VERSION 5.8 ;
BUSBITCHARS "[]" ;
DIVIDERCHAR "/" ;
UNITS
    DATABASE MICRONS 1000 ;
END UNITS

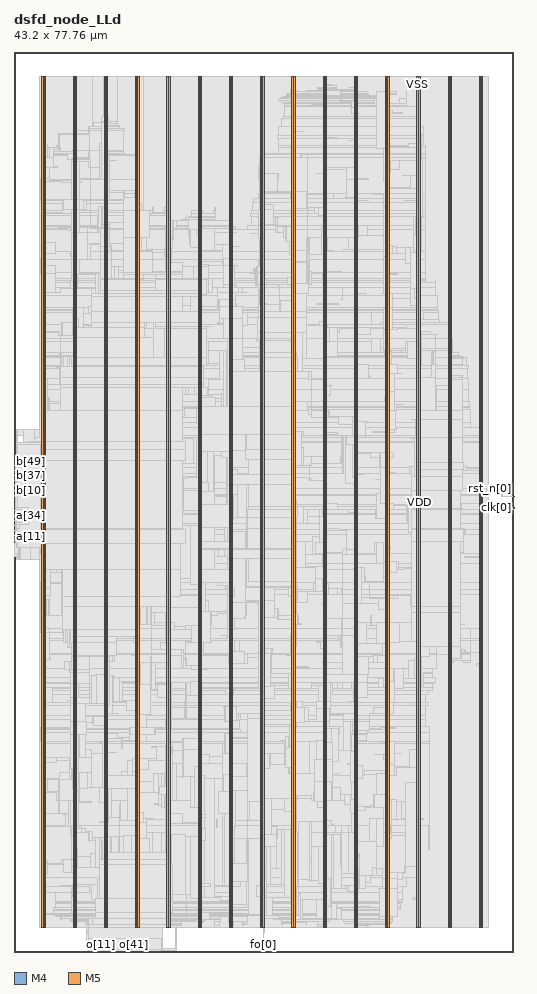
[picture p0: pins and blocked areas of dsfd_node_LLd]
MACRO dsfd_node_LLd
  FOREIGN dsfd_node_LLd 0 0 ;
  CLASS BLOCK ;
  SIZE 43.2 BY 77.76 ;
  PIN a[0]
    DIRECTION INPUT ;
    USE SIGNAL ;
    PORT
      LAYER M4 ;
        RECT  0 35.376 0.084 35.4 ;
    END
  END a[0]
  PIN a[10]
    DIRECTION INPUT ;
    USE SIGNAL ;
    PORT
      LAYER M4 ;
        RECT  0 35.856 0.084 35.88 ;
    END
  END a[10]
  PIN a[11]
    DIRECTION INPUT ;
    USE SIGNAL ;
    PORT
      LAYER M4 ;
        RECT  0 35.904 0.084 35.928 ;
    END
  END a[11]
  PIN a[12]
    DIRECTION INPUT ;
    USE SIGNAL ;
    PORT
      LAYER M4 ;
        RECT  0 35.952 0.084 35.976 ;
    END
  END a[12]
  PIN a[13]
    DIRECTION INPUT ;
    USE SIGNAL ;
    PORT
      LAYER M4 ;
        RECT  0 36 0.084 36.024 ;
    END
  END a[13]
  PIN a[14]
    DIRECTION INPUT ;
    USE SIGNAL ;
    PORT
      LAYER M4 ;
        RECT  0 36.048 0.084 36.072 ;
    END
  END a[14]
  PIN a[15]
    DIRECTION INPUT ;
    USE SIGNAL ;
    PORT
      LAYER M4 ;
        RECT  0 36.096 0.084 36.12 ;
    END
  END a[15]
  PIN a[16]
    DIRECTION INPUT ;
    USE SIGNAL ;
    PORT
      LAYER M4 ;
        RECT  0 36.144 0.084 36.168 ;
    END
  END a[16]
  PIN a[17]
    DIRECTION INPUT ;
    USE SIGNAL ;
    PORT
      LAYER M4 ;
        RECT  0 36.192 0.084 36.216 ;
    END
  END a[17]
  PIN a[18]
    DIRECTION INPUT ;
    USE SIGNAL ;
    PORT
      LAYER M4 ;
        RECT  0 36.24 0.084 36.264 ;
    END
  END a[18]
  PIN a[19]
    DIRECTION INPUT ;
    USE SIGNAL ;
    PORT
      LAYER M4 ;
        RECT  0 36.288 0.084 36.312 ;
    END
  END a[19]
  PIN a[1]
    DIRECTION INPUT ;
    USE SIGNAL ;
    PORT
      LAYER M4 ;
        RECT  0 35.424 0.084 35.448 ;
    END
  END a[1]
  PIN a[20]
    DIRECTION INPUT ;
    USE SIGNAL ;
    PORT
      LAYER M4 ;
        RECT  0 36.336 0.084 36.36 ;
    END
  END a[20]
  PIN a[21]
    DIRECTION INPUT ;
    USE SIGNAL ;
    PORT
      LAYER M4 ;
        RECT  0 36.384 0.084 36.408 ;
    END
  END a[21]
  PIN a[22]
    DIRECTION INPUT ;
    USE SIGNAL ;
    PORT
      LAYER M4 ;
        RECT  0 36.432 0.084 36.456 ;
    END
  END a[22]
  PIN a[23]
    DIRECTION INPUT ;
    USE SIGNAL ;
    PORT
      LAYER M4 ;
        RECT  0 36.48 0.084 36.504 ;
    END
  END a[23]
  PIN a[24]
    DIRECTION INPUT ;
    USE SIGNAL ;
    PORT
      LAYER M4 ;
        RECT  0 36.528 0.084 36.552 ;
    END
  END a[24]
  PIN a[25]
    DIRECTION INPUT ;
    USE SIGNAL ;
    PORT
      LAYER M4 ;
        RECT  0 36.576 0.084 36.6 ;
    END
  END a[25]
  PIN a[26]
    DIRECTION INPUT ;
    USE SIGNAL ;
    PORT
      LAYER M4 ;
        RECT  0 36.624 0.084 36.648 ;
    END
  END a[26]
  PIN a[27]
    DIRECTION INPUT ;
    USE SIGNAL ;
    PORT
      LAYER M4 ;
        RECT  0 36.672 0.084 36.696 ;
    END
  END a[27]
  PIN a[28]
    DIRECTION INPUT ;
    USE SIGNAL ;
    PORT
      LAYER M4 ;
        RECT  0 36.72 0.084 36.744 ;
    END
  END a[28]
  PIN a[29]
    DIRECTION INPUT ;
    USE SIGNAL ;
    PORT
      LAYER M4 ;
        RECT  0 36.768 0.084 36.792 ;
    END
  END a[29]
  PIN a[2]
    DIRECTION INPUT ;
    USE SIGNAL ;
    PORT
      LAYER M4 ;
        RECT  0 35.472 0.084 35.496 ;
    END
  END a[2]
  PIN a[30]
    DIRECTION INPUT ;
    USE SIGNAL ;
    PORT
      LAYER M4 ;
        RECT  0 36.816 0.084 36.84 ;
    END
  END a[30]
  PIN a[31]
    DIRECTION INPUT ;
    USE SIGNAL ;
    PORT
      LAYER M4 ;
        RECT  0 36.864 0.084 36.888 ;
    END
  END a[31]
  PIN a[32]
    DIRECTION INPUT ;
    USE SIGNAL ;
    PORT
      LAYER M4 ;
        RECT  0 36.912 0.084 36.936 ;
    END
  END a[32]
  PIN a[33]
    DIRECTION INPUT ;
    USE SIGNAL ;
    PORT
      LAYER M4 ;
        RECT  0 36.96 0.084 36.984 ;
    END
  END a[33]
  PIN a[34]
    DIRECTION INPUT ;
    USE SIGNAL ;
    PORT
      LAYER M4 ;
        RECT  0 37.008 0.084 37.032 ;
    END
  END a[34]
  PIN a[35]
    DIRECTION INPUT ;
    USE SIGNAL ;
    PORT
      LAYER M4 ;
        RECT  0 37.056 0.084 37.08 ;
    END
  END a[35]
  PIN a[36]
    DIRECTION INPUT ;
    USE SIGNAL ;
    PORT
      LAYER M4 ;
        RECT  0 37.104 0.084 37.128 ;
    END
  END a[36]
  PIN a[37]
    DIRECTION INPUT ;
    USE SIGNAL ;
    PORT
      LAYER M4 ;
        RECT  0 37.152 0.084 37.176 ;
    END
  END a[37]
  PIN a[38]
    DIRECTION INPUT ;
    USE SIGNAL ;
    PORT
      LAYER M4 ;
        RECT  0 37.2 0.084 37.224 ;
    END
  END a[38]
  PIN a[39]
    DIRECTION INPUT ;
    USE SIGNAL ;
    PORT
      LAYER M4 ;
        RECT  0 37.248 0.084 37.272 ;
    END
  END a[39]
  PIN a[3]
    DIRECTION INPUT ;
    USE SIGNAL ;
    PORT
      LAYER M4 ;
        RECT  0 35.52 0.084 35.544 ;
    END
  END a[3]
  PIN a[40]
    DIRECTION INPUT ;
    USE SIGNAL ;
    PORT
      LAYER M4 ;
        RECT  0 37.296 0.084 37.32 ;
    END
  END a[40]
  PIN a[41]
    DIRECTION INPUT ;
    USE SIGNAL ;
    PORT
      LAYER M4 ;
        RECT  0 37.344 0.084 37.368 ;
    END
  END a[41]
  PIN a[42]
    DIRECTION INPUT ;
    USE SIGNAL ;
    PORT
      LAYER M4 ;
        RECT  0 37.392 0.084 37.416 ;
    END
  END a[42]
  PIN a[43]
    DIRECTION INPUT ;
    USE SIGNAL ;
    PORT
      LAYER M4 ;
        RECT  0 37.44 0.084 37.464 ;
    END
  END a[43]
  PIN a[44]
    DIRECTION INPUT ;
    USE SIGNAL ;
    PORT
      LAYER M4 ;
        RECT  0 37.488 0.084 37.512 ;
    END
  END a[44]
  PIN a[45]
    DIRECTION INPUT ;
    USE SIGNAL ;
    PORT
      LAYER M4 ;
        RECT  0 37.536 0.084 37.56 ;
    END
  END a[45]
  PIN a[46]
    DIRECTION INPUT ;
    USE SIGNAL ;
    PORT
      LAYER M4 ;
        RECT  0 37.584 0.084 37.608 ;
    END
  END a[46]
  PIN a[47]
    DIRECTION INPUT ;
    USE SIGNAL ;
    PORT
      LAYER M4 ;
        RECT  0 37.632 0.084 37.656 ;
    END
  END a[47]
  PIN a[48]
    DIRECTION INPUT ;
    USE SIGNAL ;
    PORT
      LAYER M4 ;
        RECT  0 37.68 0.084 37.704 ;
    END
  END a[48]
  PIN a[49]
    DIRECTION INPUT ;
    USE SIGNAL ;
    PORT
      LAYER M4 ;
        RECT  0 37.728 0.084 37.752 ;
    END
  END a[49]
  PIN a[4]
    DIRECTION INPUT ;
    USE SIGNAL ;
    PORT
      LAYER M4 ;
        RECT  0 35.568 0.084 35.592 ;
    END
  END a[4]
  PIN a[50]
    DIRECTION INPUT ;
    USE SIGNAL ;
    PORT
      LAYER M4 ;
        RECT  0 37.776 0.084 37.8 ;
    END
  END a[50]
  PIN a[51]
    DIRECTION INPUT ;
    USE SIGNAL ;
    PORT
      LAYER M4 ;
        RECT  0 37.824 0.084 37.848 ;
    END
  END a[51]
  PIN a[52]
    DIRECTION INPUT ;
    USE SIGNAL ;
    PORT
      LAYER M4 ;
        RECT  0 37.872 0.084 37.896 ;
    END
  END a[52]
  PIN a[53]
    DIRECTION INPUT ;
    USE SIGNAL ;
    PORT
      LAYER M4 ;
        RECT  0 37.92 0.084 37.944 ;
    END
  END a[53]
  PIN a[54]
    DIRECTION INPUT ;
    USE SIGNAL ;
    PORT
      LAYER M4 ;
        RECT  0 37.968 0.084 37.992 ;
    END
  END a[54]
  PIN a[55]
    DIRECTION INPUT ;
    USE SIGNAL ;
    PORT
      LAYER M4 ;
        RECT  0 38.016 0.084 38.04 ;
    END
  END a[55]
  PIN a[56]
    DIRECTION INPUT ;
    USE SIGNAL ;
    PORT
      LAYER M4 ;
        RECT  0 38.064 0.084 38.088 ;
    END
  END a[56]
  PIN a[57]
    DIRECTION INPUT ;
    USE SIGNAL ;
    PORT
      LAYER M4 ;
        RECT  0 38.112 0.084 38.136 ;
    END
  END a[57]
  PIN a[58]
    DIRECTION INPUT ;
    USE SIGNAL ;
    PORT
      LAYER M4 ;
        RECT  0 38.16 0.084 38.184 ;
    END
  END a[58]
  PIN a[59]
    DIRECTION INPUT ;
    USE SIGNAL ;
    PORT
      LAYER M4 ;
        RECT  0 38.208 0.084 38.232 ;
    END
  END a[59]
  PIN a[5]
    DIRECTION INPUT ;
    USE SIGNAL ;
    PORT
      LAYER M4 ;
        RECT  0 35.616 0.084 35.64 ;
    END
  END a[5]
  PIN a[60]
    DIRECTION INPUT ;
    USE SIGNAL ;
    PORT
      LAYER M4 ;
        RECT  0 38.256 0.084 38.28 ;
    END
  END a[60]
  PIN a[61]
    DIRECTION INPUT ;
    USE SIGNAL ;
    PORT
      LAYER M4 ;
        RECT  0 38.304 0.084 38.328 ;
    END
  END a[61]
  PIN a[62]
    DIRECTION INPUT ;
    USE SIGNAL ;
    PORT
      LAYER M4 ;
        RECT  0 38.352 0.084 38.376 ;
    END
  END a[62]
  PIN a[6]
    DIRECTION INPUT ;
    USE SIGNAL ;
    PORT
      LAYER M4 ;
        RECT  0 35.664 0.084 35.688 ;
    END
  END a[6]
  PIN a[7]
    DIRECTION INPUT ;
    USE SIGNAL ;
    PORT
      LAYER M4 ;
        RECT  0 35.712 0.084 35.736 ;
    END
  END a[7]
  PIN a[8]
    DIRECTION INPUT ;
    USE SIGNAL ;
    PORT
      LAYER M4 ;
        RECT  0 35.76 0.084 35.784 ;
    END
  END a[8]
  PIN a[9]
    DIRECTION INPUT ;
    USE SIGNAL ;
    PORT
      LAYER M4 ;
        RECT  0 35.808 0.084 35.832 ;
    END
  END a[9]
  PIN b[0]
    DIRECTION INPUT ;
    USE SIGNAL ;
    PORT
      LAYER M4 ;
        RECT  0 39.36 0.084 39.384 ;
    END
  END b[0]
  PIN b[10]
    DIRECTION INPUT ;
    USE SIGNAL ;
    PORT
      LAYER M4 ;
        RECT  0 39.84 0.084 39.864 ;
    END
  END b[10]
  PIN b[11]
    DIRECTION INPUT ;
    USE SIGNAL ;
    PORT
      LAYER M4 ;
        RECT  0 39.888 0.084 39.912 ;
    END
  END b[11]
  PIN b[12]
    DIRECTION INPUT ;
    USE SIGNAL ;
    PORT
      LAYER M4 ;
        RECT  0 39.936 0.084 39.96 ;
    END
  END b[12]
  PIN b[13]
    DIRECTION INPUT ;
    USE SIGNAL ;
    PORT
      LAYER M4 ;
        RECT  0 39.984 0.084 40.008 ;
    END
  END b[13]
  PIN b[14]
    DIRECTION INPUT ;
    USE SIGNAL ;
    PORT
      LAYER M4 ;
        RECT  0 40.032 0.084 40.056 ;
    END
  END b[14]
  PIN b[15]
    DIRECTION INPUT ;
    USE SIGNAL ;
    PORT
      LAYER M4 ;
        RECT  0 40.08 0.084 40.104 ;
    END
  END b[15]
  PIN b[16]
    DIRECTION INPUT ;
    USE SIGNAL ;
    PORT
      LAYER M4 ;
        RECT  0 40.128 0.084 40.152 ;
    END
  END b[16]
  PIN b[17]
    DIRECTION INPUT ;
    USE SIGNAL ;
    PORT
      LAYER M4 ;
        RECT  0 40.176 0.084 40.2 ;
    END
  END b[17]
  PIN b[18]
    DIRECTION INPUT ;
    USE SIGNAL ;
    PORT
      LAYER M4 ;
        RECT  0 40.224 0.084 40.248 ;
    END
  END b[18]
  PIN b[19]
    DIRECTION INPUT ;
    USE SIGNAL ;
    PORT
      LAYER M4 ;
        RECT  0 40.272 0.084 40.296 ;
    END
  END b[19]
  PIN b[1]
    DIRECTION INPUT ;
    USE SIGNAL ;
    PORT
      LAYER M4 ;
        RECT  0 39.408 0.084 39.432 ;
    END
  END b[1]
  PIN b[20]
    DIRECTION INPUT ;
    USE SIGNAL ;
    PORT
      LAYER M4 ;
        RECT  0 40.32 0.084 40.344 ;
    END
  END b[20]
  PIN b[21]
    DIRECTION INPUT ;
    USE SIGNAL ;
    PORT
      LAYER M4 ;
        RECT  0 40.368 0.084 40.392 ;
    END
  END b[21]
  PIN b[22]
    DIRECTION INPUT ;
    USE SIGNAL ;
    PORT
      LAYER M4 ;
        RECT  0 40.416 0.084 40.44 ;
    END
  END b[22]
  PIN b[23]
    DIRECTION INPUT ;
    USE SIGNAL ;
    PORT
      LAYER M4 ;
        RECT  0 40.464 0.084 40.488 ;
    END
  END b[23]
  PIN b[24]
    DIRECTION INPUT ;
    USE SIGNAL ;
    PORT
      LAYER M4 ;
        RECT  0 40.512 0.084 40.536 ;
    END
  END b[24]
  PIN b[25]
    DIRECTION INPUT ;
    USE SIGNAL ;
    PORT
      LAYER M4 ;
        RECT  0 40.56 0.084 40.584 ;
    END
  END b[25]
  PIN b[26]
    DIRECTION INPUT ;
    USE SIGNAL ;
    PORT
      LAYER M4 ;
        RECT  0 40.608 0.084 40.632 ;
    END
  END b[26]
  PIN b[27]
    DIRECTION INPUT ;
    USE SIGNAL ;
    PORT
      LAYER M4 ;
        RECT  0 40.656 0.084 40.68 ;
    END
  END b[27]
  PIN b[28]
    DIRECTION INPUT ;
    USE SIGNAL ;
    PORT
      LAYER M4 ;
        RECT  0 40.704 0.084 40.728 ;
    END
  END b[28]
  PIN b[29]
    DIRECTION INPUT ;
    USE SIGNAL ;
    PORT
      LAYER M4 ;
        RECT  0 40.752 0.084 40.776 ;
    END
  END b[29]
  PIN b[2]
    DIRECTION INPUT ;
    USE SIGNAL ;
    PORT
      LAYER M4 ;
        RECT  0 39.456 0.084 39.48 ;
    END
  END b[2]
  PIN b[30]
    DIRECTION INPUT ;
    USE SIGNAL ;
    PORT
      LAYER M4 ;
        RECT  0 40.8 0.084 40.824 ;
    END
  END b[30]
  PIN b[31]
    DIRECTION INPUT ;
    USE SIGNAL ;
    PORT
      LAYER M4 ;
        RECT  0 40.848 0.084 40.872 ;
    END
  END b[31]
  PIN b[32]
    DIRECTION INPUT ;
    USE SIGNAL ;
    PORT
      LAYER M4 ;
        RECT  0 40.896 0.084 40.92 ;
    END
  END b[32]
  PIN b[33]
    DIRECTION INPUT ;
    USE SIGNAL ;
    PORT
      LAYER M4 ;
        RECT  0 40.944 0.084 40.968 ;
    END
  END b[33]
  PIN b[34]
    DIRECTION INPUT ;
    USE SIGNAL ;
    PORT
      LAYER M4 ;
        RECT  0 40.992 0.084 41.016 ;
    END
  END b[34]
  PIN b[35]
    DIRECTION INPUT ;
    USE SIGNAL ;
    PORT
      LAYER M4 ;
        RECT  0 41.04 0.084 41.064 ;
    END
  END b[35]
  PIN b[36]
    DIRECTION INPUT ;
    USE SIGNAL ;
    PORT
      LAYER M4 ;
        RECT  0 41.088 0.084 41.112 ;
    END
  END b[36]
  PIN b[37]
    DIRECTION INPUT ;
    USE SIGNAL ;
    PORT
      LAYER M4 ;
        RECT  0 41.136 0.084 41.16 ;
    END
  END b[37]
  PIN b[38]
    DIRECTION INPUT ;
    USE SIGNAL ;
    PORT
      LAYER M4 ;
        RECT  0 41.184 0.084 41.208 ;
    END
  END b[38]
  PIN b[39]
    DIRECTION INPUT ;
    USE SIGNAL ;
    PORT
      LAYER M4 ;
        RECT  0 41.232 0.084 41.256 ;
    END
  END b[39]
  PIN b[3]
    DIRECTION INPUT ;
    USE SIGNAL ;
    PORT
      LAYER M4 ;
        RECT  0 39.504 0.084 39.528 ;
    END
  END b[3]
  PIN b[40]
    DIRECTION INPUT ;
    USE SIGNAL ;
    PORT
      LAYER M4 ;
        RECT  0 41.28 0.084 41.304 ;
    END
  END b[40]
  PIN b[41]
    DIRECTION INPUT ;
    USE SIGNAL ;
    PORT
      LAYER M4 ;
        RECT  0 41.328 0.084 41.352 ;
    END
  END b[41]
  PIN b[42]
    DIRECTION INPUT ;
    USE SIGNAL ;
    PORT
      LAYER M4 ;
        RECT  0 41.376 0.084 41.4 ;
    END
  END b[42]
  PIN b[43]
    DIRECTION INPUT ;
    USE SIGNAL ;
    PORT
      LAYER M4 ;
        RECT  0 41.424 0.084 41.448 ;
    END
  END b[43]
  PIN b[44]
    DIRECTION INPUT ;
    USE SIGNAL ;
    PORT
      LAYER M4 ;
        RECT  0 41.472 0.084 41.496 ;
    END
  END b[44]
  PIN b[45]
    DIRECTION INPUT ;
    USE SIGNAL ;
    PORT
      LAYER M4 ;
        RECT  0 41.52 0.084 41.544 ;
    END
  END b[45]
  PIN b[46]
    DIRECTION INPUT ;
    USE SIGNAL ;
    PORT
      LAYER M4 ;
        RECT  0 41.568 0.084 41.592 ;
    END
  END b[46]
  PIN b[47]
    DIRECTION INPUT ;
    USE SIGNAL ;
    PORT
      LAYER M4 ;
        RECT  0 41.616 0.084 41.64 ;
    END
  END b[47]
  PIN b[48]
    DIRECTION INPUT ;
    USE SIGNAL ;
    PORT
      LAYER M4 ;
        RECT  0 41.664 0.084 41.688 ;
    END
  END b[48]
  PIN b[49]
    DIRECTION INPUT ;
    USE SIGNAL ;
    PORT
      LAYER M4 ;
        RECT  0 41.712 0.084 41.736 ;
    END
  END b[49]
  PIN b[4]
    DIRECTION INPUT ;
    USE SIGNAL ;
    PORT
      LAYER M4 ;
        RECT  0 39.552 0.084 39.576 ;
    END
  END b[4]
  PIN b[50]
    DIRECTION INPUT ;
    USE SIGNAL ;
    PORT
      LAYER M4 ;
        RECT  0 41.76 0.084 41.784 ;
    END
  END b[50]
  PIN b[51]
    DIRECTION INPUT ;
    USE SIGNAL ;
    PORT
      LAYER M4 ;
        RECT  0 41.808 0.084 41.832 ;
    END
  END b[51]
  PIN b[52]
    DIRECTION INPUT ;
    USE SIGNAL ;
    PORT
      LAYER M4 ;
        RECT  0 41.856 0.084 41.88 ;
    END
  END b[52]
  PIN b[53]
    DIRECTION INPUT ;
    USE SIGNAL ;
    PORT
      LAYER M4 ;
        RECT  0 41.904 0.084 41.928 ;
    END
  END b[53]
  PIN b[54]
    DIRECTION INPUT ;
    USE SIGNAL ;
    PORT
      LAYER M4 ;
        RECT  0 41.952 0.084 41.976 ;
    END
  END b[54]
  PIN b[55]
    DIRECTION INPUT ;
    USE SIGNAL ;
    PORT
      LAYER M4 ;
        RECT  0 42 0.084 42.024 ;
    END
  END b[55]
  PIN b[56]
    DIRECTION INPUT ;
    USE SIGNAL ;
    PORT
      LAYER M4 ;
        RECT  0 42.048 0.084 42.072 ;
    END
  END b[56]
  PIN b[57]
    DIRECTION INPUT ;
    USE SIGNAL ;
    PORT
      LAYER M4 ;
        RECT  0 42.096 0.084 42.12 ;
    END
  END b[57]
  PIN b[58]
    DIRECTION INPUT ;
    USE SIGNAL ;
    PORT
      LAYER M4 ;
        RECT  0 42.144 0.084 42.168 ;
    END
  END b[58]
  PIN b[59]
    DIRECTION INPUT ;
    USE SIGNAL ;
    PORT
      LAYER M4 ;
        RECT  0 42.192 0.084 42.216 ;
    END
  END b[59]
  PIN b[5]
    DIRECTION INPUT ;
    USE SIGNAL ;
    PORT
      LAYER M4 ;
        RECT  0 39.6 0.084 39.624 ;
    END
  END b[5]
  PIN b[60]
    DIRECTION INPUT ;
    USE SIGNAL ;
    PORT
      LAYER M4 ;
        RECT  0 42.24 0.084 42.264 ;
    END
  END b[60]
  PIN b[61]
    DIRECTION INPUT ;
    USE SIGNAL ;
    PORT
      LAYER M4 ;
        RECT  0 42.288 0.084 42.312 ;
    END
  END b[61]
  PIN b[62]
    DIRECTION INPUT ;
    USE SIGNAL ;
    PORT
      LAYER M4 ;
        RECT  0 42.336 0.084 42.36 ;
    END
  END b[62]
  PIN b[6]
    DIRECTION INPUT ;
    USE SIGNAL ;
    PORT
      LAYER M4 ;
        RECT  0 39.648 0.084 39.672 ;
    END
  END b[6]
  PIN b[7]
    DIRECTION INPUT ;
    USE SIGNAL ;
    PORT
      LAYER M4 ;
        RECT  0 39.696 0.084 39.72 ;
    END
  END b[7]
  PIN b[8]
    DIRECTION INPUT ;
    USE SIGNAL ;
    PORT
      LAYER M4 ;
        RECT  0 39.744 0.084 39.768 ;
    END
  END b[8]
  PIN b[9]
    DIRECTION INPUT ;
    USE SIGNAL ;
    PORT
      LAYER M4 ;
        RECT  0 39.792 0.084 39.816 ;
    END
  END b[9]
  PIN clk[0]
    DIRECTION INPUT ;
    USE SIGNAL ;
    PORT
      LAYER M4 ;
        RECT  43.116 38.352 43.2 38.376 ;
    END
  END clk[0]
  PIN fo[0]
    DIRECTION OUTPUT ;
    USE SIGNAL ;
    PORT
      LAYER M5 ;
        RECT  21.552 0 21.576 0.084 ;
    END
  END fo[0]
  PIN o[0]
    DIRECTION OUTPUT ;
    USE SIGNAL ;
    PORT
      LAYER M5 ;
        RECT  6.432 0 6.456 0.084 ;
    END
  END o[0]
  PIN o[10]
    DIRECTION OUTPUT ;
    USE SIGNAL ;
    PORT
      LAYER M5 ;
        RECT  7.392 0 7.416 0.084 ;
    END
  END o[10]
  PIN o[11]
    DIRECTION OUTPUT ;
    USE SIGNAL ;
    PORT
      LAYER M5 ;
        RECT  7.488 0 7.512 0.084 ;
    END
  END o[11]
  PIN o[12]
    DIRECTION OUTPUT ;
    USE SIGNAL ;
    PORT
      LAYER M5 ;
        RECT  7.584 0 7.608 0.084 ;
    END
  END o[12]
  PIN o[13]
    DIRECTION OUTPUT ;
    USE SIGNAL ;
    PORT
      LAYER M5 ;
        RECT  7.68 0 7.704 0.084 ;
    END
  END o[13]
  PIN o[14]
    DIRECTION OUTPUT ;
    USE SIGNAL ;
    PORT
      LAYER M5 ;
        RECT  7.776 0 7.8 0.084 ;
    END
  END o[14]
  PIN o[15]
    DIRECTION OUTPUT ;
    USE SIGNAL ;
    PORT
      LAYER M5 ;
        RECT  7.872 0 7.896 0.084 ;
    END
  END o[15]
  PIN o[16]
    DIRECTION OUTPUT ;
    USE SIGNAL ;
    PORT
      LAYER M5 ;
        RECT  7.968 0 7.992 0.084 ;
    END
  END o[16]
  PIN o[17]
    DIRECTION OUTPUT ;
    USE SIGNAL ;
    PORT
      LAYER M5 ;
        RECT  8.064 0 8.088 0.084 ;
    END
  END o[17]
  PIN o[18]
    DIRECTION OUTPUT ;
    USE SIGNAL ;
    PORT
      LAYER M5 ;
        RECT  8.16 0 8.184 0.084 ;
    END
  END o[18]
  PIN o[19]
    DIRECTION OUTPUT ;
    USE SIGNAL ;
    PORT
      LAYER M5 ;
        RECT  8.256 0 8.28 0.084 ;
    END
  END o[19]
  PIN o[1]
    DIRECTION OUTPUT ;
    USE SIGNAL ;
    PORT
      LAYER M5 ;
        RECT  6.528 0 6.552 0.084 ;
    END
  END o[1]
  PIN o[20]
    DIRECTION OUTPUT ;
    USE SIGNAL ;
    PORT
      LAYER M5 ;
        RECT  8.352 0 8.376 0.084 ;
    END
  END o[20]
  PIN o[21]
    DIRECTION OUTPUT ;
    USE SIGNAL ;
    PORT
      LAYER M5 ;
        RECT  8.448 0 8.472 0.084 ;
    END
  END o[21]
  PIN o[22]
    DIRECTION OUTPUT ;
    USE SIGNAL ;
    PORT
      LAYER M5 ;
        RECT  8.544 0 8.568 0.084 ;
    END
  END o[22]
  PIN o[23]
    DIRECTION OUTPUT ;
    USE SIGNAL ;
    PORT
      LAYER M5 ;
        RECT  8.64 0 8.664 0.084 ;
    END
  END o[23]
  PIN o[24]
    DIRECTION OUTPUT ;
    USE SIGNAL ;
    PORT
      LAYER M5 ;
        RECT  8.736 0 8.76 0.084 ;
    END
  END o[24]
  PIN o[25]
    DIRECTION OUTPUT ;
    USE SIGNAL ;
    PORT
      LAYER M5 ;
        RECT  8.832 0 8.856 0.084 ;
    END
  END o[25]
  PIN o[26]
    DIRECTION OUTPUT ;
    USE SIGNAL ;
    PORT
      LAYER M5 ;
        RECT  8.928 0 8.952 0.084 ;
    END
  END o[26]
  PIN o[27]
    DIRECTION OUTPUT ;
    USE SIGNAL ;
    PORT
      LAYER M5 ;
        RECT  9.024 0 9.048 0.084 ;
    END
  END o[27]
  PIN o[28]
    DIRECTION OUTPUT ;
    USE SIGNAL ;
    PORT
      LAYER M5 ;
        RECT  9.12 0 9.144 0.084 ;
    END
  END o[28]
  PIN o[29]
    DIRECTION OUTPUT ;
    USE SIGNAL ;
    PORT
      LAYER M5 ;
        RECT  9.216 0 9.24 0.084 ;
    END
  END o[29]
  PIN o[2]
    DIRECTION OUTPUT ;
    USE SIGNAL ;
    PORT
      LAYER M5 ;
        RECT  6.624 0 6.648 0.084 ;
    END
  END o[2]
  PIN o[30]
    DIRECTION OUTPUT ;
    USE SIGNAL ;
    PORT
      LAYER M5 ;
        RECT  9.312 0 9.336 0.084 ;
    END
  END o[30]
  PIN o[31]
    DIRECTION OUTPUT ;
    USE SIGNAL ;
    PORT
      LAYER M5 ;
        RECT  9.408 0 9.432 0.084 ;
    END
  END o[31]
  PIN o[32]
    DIRECTION OUTPUT ;
    USE SIGNAL ;
    PORT
      LAYER M5 ;
        RECT  9.504 0 9.528 0.084 ;
    END
  END o[32]
  PIN o[33]
    DIRECTION OUTPUT ;
    USE SIGNAL ;
    PORT
      LAYER M5 ;
        RECT  9.6 0 9.624 0.084 ;
    END
  END o[33]
  PIN o[34]
    DIRECTION OUTPUT ;
    USE SIGNAL ;
    PORT
      LAYER M5 ;
        RECT  9.696 0 9.72 0.084 ;
    END
  END o[34]
  PIN o[35]
    DIRECTION OUTPUT ;
    USE SIGNAL ;
    PORT
      LAYER M5 ;
        RECT  9.792 0 9.816 0.084 ;
    END
  END o[35]
  PIN o[36]
    DIRECTION OUTPUT ;
    USE SIGNAL ;
    PORT
      LAYER M5 ;
        RECT  9.888 0 9.912 0.084 ;
    END
  END o[36]
  PIN o[37]
    DIRECTION OUTPUT ;
    USE SIGNAL ;
    PORT
      LAYER M5 ;
        RECT  9.984 0 10.008 0.084 ;
    END
  END o[37]
  PIN o[38]
    DIRECTION OUTPUT ;
    USE SIGNAL ;
    PORT
      LAYER M5 ;
        RECT  10.08 0 10.104 0.084 ;
    END
  END o[38]
  PIN o[39]
    DIRECTION OUTPUT ;
    USE SIGNAL ;
    PORT
      LAYER M5 ;
        RECT  10.176 0 10.2 0.084 ;
    END
  END o[39]
  PIN o[3]
    DIRECTION OUTPUT ;
    USE SIGNAL ;
    PORT
      LAYER M5 ;
        RECT  6.72 0 6.744 0.084 ;
    END
  END o[3]
  PIN o[40]
    DIRECTION OUTPUT ;
    USE SIGNAL ;
    PORT
      LAYER M5 ;
        RECT  10.272 0 10.296 0.084 ;
    END
  END o[40]
  PIN o[41]
    DIRECTION OUTPUT ;
    USE SIGNAL ;
    PORT
      LAYER M5 ;
        RECT  10.368 0 10.392 0.084 ;
    END
  END o[41]
  PIN o[42]
    DIRECTION OUTPUT ;
    USE SIGNAL ;
    PORT
      LAYER M5 ;
        RECT  10.464 0 10.488 0.084 ;
    END
  END o[42]
  PIN o[43]
    DIRECTION OUTPUT ;
    USE SIGNAL ;
    PORT
      LAYER M5 ;
        RECT  10.56 0 10.584 0.084 ;
    END
  END o[43]
  PIN o[44]
    DIRECTION OUTPUT ;
    USE SIGNAL ;
    PORT
      LAYER M5 ;
        RECT  10.656 0 10.68 0.084 ;
    END
  END o[44]
  PIN o[45]
    DIRECTION OUTPUT ;
    USE SIGNAL ;
    PORT
      LAYER M5 ;
        RECT  10.752 0 10.776 0.084 ;
    END
  END o[45]
  PIN o[46]
    DIRECTION OUTPUT ;
    USE SIGNAL ;
    PORT
      LAYER M5 ;
        RECT  10.848 0 10.872 0.084 ;
    END
  END o[46]
  PIN o[47]
    DIRECTION OUTPUT ;
    USE SIGNAL ;
    PORT
      LAYER M5 ;
        RECT  10.944 0 10.968 0.084 ;
    END
  END o[47]
  PIN o[48]
    DIRECTION OUTPUT ;
    USE SIGNAL ;
    PORT
      LAYER M5 ;
        RECT  11.04 0 11.064 0.084 ;
    END
  END o[48]
  PIN o[49]
    DIRECTION OUTPUT ;
    USE SIGNAL ;
    PORT
      LAYER M5 ;
        RECT  11.136 0 11.16 0.084 ;
    END
  END o[49]
  PIN o[4]
    DIRECTION OUTPUT ;
    USE SIGNAL ;
    PORT
      LAYER M5 ;
        RECT  6.816 0 6.84 0.084 ;
    END
  END o[4]
  PIN o[50]
    DIRECTION OUTPUT ;
    USE SIGNAL ;
    PORT
      LAYER M5 ;
        RECT  11.232 0 11.256 0.084 ;
    END
  END o[50]
  PIN o[51]
    DIRECTION OUTPUT ;
    USE SIGNAL ;
    PORT
      LAYER M5 ;
        RECT  11.328 0 11.352 0.084 ;
    END
  END o[51]
  PIN o[52]
    DIRECTION OUTPUT ;
    USE SIGNAL ;
    PORT
      LAYER M5 ;
        RECT  11.424 0 11.448 0.084 ;
    END
  END o[52]
  PIN o[53]
    DIRECTION OUTPUT ;
    USE SIGNAL ;
    PORT
      LAYER M5 ;
        RECT  11.52 0 11.544 0.084 ;
    END
  END o[53]
  PIN o[54]
    DIRECTION OUTPUT ;
    USE SIGNAL ;
    PORT
      LAYER M5 ;
        RECT  11.616 0 11.64 0.084 ;
    END
  END o[54]
  PIN o[55]
    DIRECTION OUTPUT ;
    USE SIGNAL ;
    PORT
      LAYER M5 ;
        RECT  11.712 0 11.736 0.084 ;
    END
  END o[55]
  PIN o[56]
    DIRECTION OUTPUT ;
    USE SIGNAL ;
    PORT
      LAYER M5 ;
        RECT  11.808 0 11.832 0.084 ;
    END
  END o[56]
  PIN o[57]
    DIRECTION OUTPUT ;
    USE SIGNAL ;
    PORT
      LAYER M5 ;
        RECT  11.904 0 11.928 0.084 ;
    END
  END o[57]
  PIN o[58]
    DIRECTION OUTPUT ;
    USE SIGNAL ;
    PORT
      LAYER M5 ;
        RECT  12 0 12.024 0.084 ;
    END
  END o[58]
  PIN o[59]
    DIRECTION OUTPUT ;
    USE SIGNAL ;
    PORT
      LAYER M5 ;
        RECT  12.096 0 12.12 0.084 ;
    END
  END o[59]
  PIN o[5]
    DIRECTION OUTPUT ;
    USE SIGNAL ;
    PORT
      LAYER M5 ;
        RECT  6.912 0 6.936 0.084 ;
    END
  END o[5]
  PIN o[60]
    DIRECTION OUTPUT ;
    USE SIGNAL ;
    PORT
      LAYER M5 ;
        RECT  12.192 0 12.216 0.084 ;
    END
  END o[60]
  PIN o[61]
    DIRECTION OUTPUT ;
    USE SIGNAL ;
    PORT
      LAYER M5 ;
        RECT  12.288 0 12.312 0.084 ;
    END
  END o[61]
  PIN o[62]
    DIRECTION OUTPUT ;
    USE SIGNAL ;
    PORT
      LAYER M5 ;
        RECT  12.384 0 12.408 0.084 ;
    END
  END o[62]
  PIN o[63]
    DIRECTION OUTPUT ;
    USE SIGNAL ;
    PORT
      LAYER M5 ;
        RECT  12.48 0 12.504 0.084 ;
    END
  END o[63]
  PIN o[64]
    DIRECTION OUTPUT ;
    USE SIGNAL ;
    PORT
      LAYER M5 ;
        RECT  12.576 0 12.6 0.084 ;
    END
  END o[64]
  PIN o[65]
    DIRECTION OUTPUT ;
    USE SIGNAL ;
    PORT
      LAYER M5 ;
        RECT  12.672 0 12.696 0.084 ;
    END
  END o[65]
  PIN o[6]
    DIRECTION OUTPUT ;
    USE SIGNAL ;
    PORT
      LAYER M5 ;
        RECT  7.008 0 7.032 0.084 ;
    END
  END o[6]
  PIN o[7]
    DIRECTION OUTPUT ;
    USE SIGNAL ;
    PORT
      LAYER M5 ;
        RECT  7.104 0 7.128 0.084 ;
    END
  END o[7]
  PIN o[8]
    DIRECTION OUTPUT ;
    USE SIGNAL ;
    PORT
      LAYER M5 ;
        RECT  7.2 0 7.224 0.084 ;
    END
  END o[8]
  PIN o[9]
    DIRECTION OUTPUT ;
    USE SIGNAL ;
    PORT
      LAYER M5 ;
        RECT  7.296 0 7.32 0.084 ;
    END
  END o[9]
  PIN rst_n[0]
    DIRECTION INPUT ;
    USE SIGNAL ;
    PORT
      LAYER M4 ;
        RECT  43.116 39.36 43.2 39.384 ;
    END
  END rst_n[0]
  PIN VDD
    DIRECTION INOUT ;
    USE POWER ;
    PORT
      LAYER M5 ;
        RECT  40.392 2.151 40.512 75.609 ;
        RECT  37.692 2.151 37.812 75.609 ;
        RECT  34.992 2.151 35.112 75.609 ;
        RECT  32.292 2.151 32.412 75.609 ;
        RECT  29.592 2.151 29.712 75.609 ;
        RECT  26.892 2.151 27.012 75.609 ;
        RECT  24.192 2.151 24.312 75.609 ;
        RECT  21.492 2.151 21.612 75.609 ;
        RECT  18.792 2.151 18.912 75.609 ;
        RECT  16.092 2.151 16.212 75.609 ;
        RECT  13.392 2.151 13.512 75.609 ;
        RECT  10.692 2.151 10.812 75.609 ;
        RECT  7.992 2.151 8.112 75.609 ;
        RECT  5.292 2.151 5.412 75.609 ;
        RECT  2.592 2.151 2.712 75.609 ;
    END
  END VDD
  PIN VSS
    DIRECTION INOUT ;
    USE GROUND ;
    PORT
      LAYER M5 ;
        RECT  40.2 2.137 40.32 75.623 ;
        RECT  37.5 2.137 37.62 75.623 ;
        RECT  34.8 2.137 34.92 75.623 ;
        RECT  32.1 2.137 32.22 75.623 ;
        RECT  29.4 2.137 29.52 75.623 ;
        RECT  26.7 2.137 26.82 75.623 ;
        RECT  24 2.137 24.12 75.623 ;
        RECT  21.3 2.137 21.42 75.623 ;
        RECT  18.6 2.137 18.72 75.623 ;
        RECT  15.9 2.137 16.02 75.623 ;
        RECT  13.2 2.137 13.32 75.623 ;
        RECT  10.5 2.137 10.62 75.623 ;
        RECT  7.8 2.137 7.92 75.623 ;
        RECT  5.1 2.137 5.22 75.623 ;
        RECT  2.4 2.137 2.52 75.623 ;
    END
  END VSS
  OBS
    LAYER RVTN ;
     RECT  2.16 2.16 41.04 2.295 ;
     RECT  2.16 2.565 41.04 2.835 ;
     RECT  2.16 3.105 41.04 3.375 ;
     RECT  2.16 3.645 41.04 3.915 ;
     RECT  2.16 4.185 41.04 4.455 ;
     RECT  2.16 4.725 41.04 4.995 ;
     RECT  2.16 5.265 41.04 5.535 ;
     RECT  2.16 5.805 41.04 6.075 ;
     RECT  2.16 6.345 41.04 6.615 ;
     RECT  2.16 6.885 41.04 7.155 ;
     RECT  2.16 7.425 41.04 7.695 ;
     RECT  2.16 7.965 41.04 8.235 ;
     RECT  2.16 8.505 41.04 8.775 ;
     RECT  2.16 9.045 41.04 9.315 ;
     RECT  2.16 9.585 41.04 9.855 ;
     RECT  2.16 10.125 41.04 10.395 ;
     RECT  2.16 10.665 41.04 10.935 ;
     RECT  2.16 11.205 41.04 11.475 ;
     RECT  2.16 11.745 41.04 12.015 ;
     RECT  2.16 12.285 41.04 12.555 ;
     RECT  2.16 12.825 41.04 13.095 ;
     RECT  2.16 13.365 41.04 13.635 ;
     RECT  2.16 13.905 41.04 14.175 ;
     RECT  2.16 14.445 41.04 14.715 ;
     RECT  2.16 14.985 41.04 15.255 ;
     RECT  2.16 15.525 41.04 15.795 ;
     RECT  2.16 16.065 41.04 16.335 ;
     RECT  2.16 16.605 41.04 16.875 ;
     RECT  2.16 17.145 41.04 17.415 ;
     RECT  2.16 17.685 41.04 17.955 ;
     RECT  2.16 18.225 41.04 18.495 ;
     RECT  2.16 18.765 41.04 19.035 ;
     RECT  2.16 19.305 41.04 19.575 ;
     RECT  2.16 19.845 41.04 20.115 ;
     RECT  2.16 20.385 41.04 20.655 ;
     RECT  2.16 20.925 41.04 21.195 ;
     RECT  2.16 21.465 41.04 21.735 ;
     RECT  2.16 22.005 41.04 22.275 ;
     RECT  2.16 22.545 41.04 22.815 ;
     RECT  2.16 23.085 41.04 23.355 ;
     RECT  2.16 23.625 41.04 23.895 ;
     RECT  2.16 24.165 41.04 24.435 ;
     RECT  2.16 24.705 41.04 24.975 ;
     RECT  2.16 25.245 41.04 25.515 ;
     RECT  2.16 25.785 41.04 26.055 ;
     RECT  2.16 26.325 41.04 26.595 ;
     RECT  2.16 26.865 41.04 27.135 ;
     RECT  2.16 27.405 41.04 27.675 ;
     RECT  2.16 27.945 41.04 28.215 ;
     RECT  2.16 28.485 41.04 28.755 ;
     RECT  2.16 29.025 41.04 29.295 ;
     RECT  2.16 29.565 41.04 29.835 ;
     RECT  2.16 30.105 41.04 30.375 ;
     RECT  2.16 30.645 41.04 30.915 ;
     RECT  2.16 31.185 41.04 31.455 ;
     RECT  2.16 31.725 41.04 31.995 ;
     RECT  2.16 32.265 41.04 32.535 ;
     RECT  2.16 32.805 41.04 33.075 ;
     RECT  2.16 33.345 41.04 33.615 ;
     RECT  2.16 33.885 41.04 34.155 ;
     RECT  2.16 34.425 41.04 34.695 ;
     RECT  2.16 34.965 41.04 35.235 ;
     RECT  2.16 35.505 41.04 35.775 ;
     RECT  2.16 36.045 41.04 36.315 ;
     RECT  2.16 36.585 41.04 36.855 ;
     RECT  2.16 37.125 41.04 37.395 ;
     RECT  2.16 37.665 41.04 37.935 ;
     RECT  2.16 38.205 41.04 38.475 ;
     RECT  2.16 38.745 41.04 39.015 ;
     RECT  2.16 39.285 41.04 39.555 ;
     RECT  2.16 39.825 41.04 40.095 ;
     RECT  2.16 40.365 41.04 40.635 ;
     RECT  2.16 40.905 41.04 41.175 ;
     RECT  2.16 41.445 41.04 41.715 ;
     RECT  2.16 41.985 41.04 42.255 ;
     RECT  2.16 42.525 41.04 42.795 ;
     RECT  2.16 43.065 41.04 43.335 ;
     RECT  2.16 43.605 41.04 43.875 ;
     RECT  2.16 44.145 41.04 44.415 ;
     RECT  2.16 44.685 41.04 44.955 ;
     RECT  2.16 45.225 41.04 45.495 ;
     RECT  2.16 45.765 41.04 46.035 ;
     RECT  2.16 46.305 41.04 46.575 ;
     RECT  2.16 46.845 41.04 47.115 ;
     RECT  2.16 47.385 41.04 47.655 ;
     RECT  2.16 47.925 41.04 48.195 ;
     RECT  2.16 48.465 41.04 48.735 ;
     RECT  2.16 49.005 41.04 49.275 ;
     RECT  2.16 49.545 41.04 49.815 ;
     RECT  2.16 50.085 41.04 50.355 ;
     RECT  2.16 50.625 41.04 50.895 ;
     RECT  2.16 51.165 41.04 51.435 ;
     RECT  2.16 51.705 41.04 51.975 ;
     RECT  2.16 52.245 41.04 52.515 ;
     RECT  2.16 52.785 41.04 53.055 ;
     RECT  2.16 53.325 41.04 53.595 ;
     RECT  2.16 53.865 41.04 54.135 ;
     RECT  2.16 54.405 41.04 54.675 ;
     RECT  2.16 54.945 41.04 55.215 ;
     RECT  2.16 55.485 41.04 55.755 ;
     RECT  2.16 56.025 41.04 56.295 ;
     RECT  2.16 56.565 41.04 56.835 ;
     RECT  2.16 57.105 41.04 57.375 ;
     RECT  2.16 57.645 41.04 57.915 ;
     RECT  2.16 58.185 41.04 58.455 ;
     RECT  2.16 58.725 41.04 58.995 ;
     RECT  2.16 59.265 41.04 59.535 ;
     RECT  2.16 59.805 41.04 60.075 ;
     RECT  2.16 60.345 41.04 60.615 ;
     RECT  2.16 60.885 41.04 61.155 ;
     RECT  2.16 61.425 41.04 61.695 ;
     RECT  2.16 61.965 41.04 62.235 ;
     RECT  2.16 62.505 41.04 62.775 ;
     RECT  2.16 63.045 41.04 63.315 ;
     RECT  2.16 63.585 41.04 63.855 ;
     RECT  2.16 64.125 41.04 64.395 ;
     RECT  2.16 64.665 41.04 64.935 ;
     RECT  2.16 65.205 41.04 65.475 ;
     RECT  2.16 65.745 41.04 66.015 ;
     RECT  2.16 66.285 41.04 66.555 ;
     RECT  2.16 66.825 41.04 67.095 ;
     RECT  2.16 67.365 41.04 67.635 ;
     RECT  2.16 67.905 41.04 68.175 ;
     RECT  2.16 68.445 41.04 68.715 ;
     RECT  2.16 68.985 41.04 69.255 ;
     RECT  2.16 69.525 41.04 69.795 ;
     RECT  2.16 70.065 41.04 70.335 ;
     RECT  2.16 70.605 41.04 70.875 ;
     RECT  2.16 71.145 41.04 71.415 ;
     RECT  2.16 71.685 41.04 71.955 ;
     RECT  2.16 72.225 41.04 72.495 ;
     RECT  2.16 72.765 41.04 73.035 ;
     RECT  2.16 73.305 41.04 73.575 ;
     RECT  2.16 73.845 41.04 74.115 ;
     RECT  2.16 74.385 41.04 74.655 ;
     RECT  2.16 74.925 41.04 75.195 ;
     RECT  2.16 75.465 41.04 75.6 ;
    LAYER RVTP ;
     RECT  2.16 2.295 41.04 2.565 ;
     RECT  2.16 2.835 41.04 3.105 ;
     RECT  2.16 3.375 41.04 3.645 ;
     RECT  2.16 3.915 41.04 4.185 ;
     RECT  2.16 4.455 41.04 4.725 ;
     RECT  2.16 4.995 41.04 5.265 ;
     RECT  2.16 5.535 41.04 5.805 ;
     RECT  2.16 6.075 41.04 6.345 ;
     RECT  2.16 6.615 41.04 6.885 ;
     RECT  2.16 7.155 41.04 7.425 ;
     RECT  2.16 7.695 41.04 7.965 ;
     RECT  2.16 8.235 41.04 8.505 ;
     RECT  2.16 8.775 41.04 9.045 ;
     RECT  2.16 9.315 41.04 9.585 ;
     RECT  2.16 9.855 41.04 10.125 ;
     RECT  2.16 10.395 41.04 10.665 ;
     RECT  2.16 10.935 41.04 11.205 ;
     RECT  2.16 11.475 41.04 11.745 ;
     RECT  2.16 12.015 41.04 12.285 ;
     RECT  2.16 12.555 41.04 12.825 ;
     RECT  2.16 13.095 41.04 13.365 ;
     RECT  2.16 13.635 41.04 13.905 ;
     RECT  2.16 14.175 41.04 14.445 ;
     RECT  2.16 14.715 41.04 14.985 ;
     RECT  2.16 15.255 41.04 15.525 ;
     RECT  2.16 15.795 41.04 16.065 ;
     RECT  2.16 16.335 41.04 16.605 ;
     RECT  2.16 16.875 41.04 17.145 ;
     RECT  2.16 17.415 41.04 17.685 ;
     RECT  2.16 17.955 41.04 18.225 ;
     RECT  2.16 18.495 41.04 18.765 ;
     RECT  2.16 19.035 41.04 19.305 ;
     RECT  2.16 19.575 41.04 19.845 ;
     RECT  2.16 20.115 41.04 20.385 ;
     RECT  2.16 20.655 41.04 20.925 ;
     RECT  2.16 21.195 41.04 21.465 ;
     RECT  2.16 21.735 41.04 22.005 ;
     RECT  2.16 22.275 41.04 22.545 ;
     RECT  2.16 22.815 41.04 23.085 ;
     RECT  2.16 23.355 41.04 23.625 ;
     RECT  2.16 23.895 41.04 24.165 ;
     RECT  2.16 24.435 41.04 24.705 ;
     RECT  2.16 24.975 41.04 25.245 ;
     RECT  2.16 25.515 41.04 25.785 ;
     RECT  2.16 26.055 41.04 26.325 ;
     RECT  2.16 26.595 41.04 26.865 ;
     RECT  2.16 27.135 41.04 27.405 ;
     RECT  2.16 27.675 41.04 27.945 ;
     RECT  2.16 28.215 41.04 28.485 ;
     RECT  2.16 28.755 41.04 29.025 ;
     RECT  2.16 29.295 41.04 29.565 ;
     RECT  2.16 29.835 41.04 30.105 ;
     RECT  2.16 30.375 41.04 30.645 ;
     RECT  2.16 30.915 41.04 31.185 ;
     RECT  2.16 31.455 41.04 31.725 ;
     RECT  2.16 31.995 41.04 32.265 ;
     RECT  2.16 32.535 41.04 32.805 ;
     RECT  2.16 33.075 41.04 33.345 ;
     RECT  2.16 33.615 41.04 33.885 ;
     RECT  2.16 34.155 41.04 34.425 ;
     RECT  2.16 34.695 41.04 34.965 ;
     RECT  2.16 35.235 41.04 35.505 ;
     RECT  2.16 35.775 41.04 36.045 ;
     RECT  2.16 36.315 41.04 36.585 ;
     RECT  2.16 36.855 41.04 37.125 ;
     RECT  2.16 37.395 41.04 37.665 ;
     RECT  2.16 37.935 41.04 38.205 ;
     RECT  2.16 38.475 41.04 38.745 ;
     RECT  2.16 39.015 41.04 39.285 ;
     RECT  2.16 39.555 41.04 39.825 ;
     RECT  2.16 40.095 41.04 40.365 ;
     RECT  2.16 40.635 41.04 40.905 ;
     RECT  2.16 41.175 41.04 41.445 ;
     RECT  2.16 41.715 41.04 41.985 ;
     RECT  2.16 42.255 41.04 42.525 ;
     RECT  2.16 42.795 41.04 43.065 ;
     RECT  2.16 43.335 41.04 43.605 ;
     RECT  2.16 43.875 41.04 44.145 ;
     RECT  2.16 44.415 41.04 44.685 ;
     RECT  2.16 44.955 41.04 45.225 ;
     RECT  2.16 45.495 41.04 45.765 ;
     RECT  2.16 46.035 41.04 46.305 ;
     RECT  2.16 46.575 41.04 46.845 ;
     RECT  2.16 47.115 41.04 47.385 ;
     RECT  2.16 47.655 41.04 47.925 ;
     RECT  2.16 48.195 41.04 48.465 ;
     RECT  2.16 48.735 41.04 49.005 ;
     RECT  2.16 49.275 41.04 49.545 ;
     RECT  2.16 49.815 41.04 50.085 ;
     RECT  2.16 50.355 41.04 50.625 ;
     RECT  2.16 50.895 41.04 51.165 ;
     RECT  2.16 51.435 41.04 51.705 ;
     RECT  2.16 51.975 41.04 52.245 ;
     RECT  2.16 52.515 41.04 52.785 ;
     RECT  2.16 53.055 41.04 53.325 ;
     RECT  2.16 53.595 41.04 53.865 ;
     RECT  2.16 54.135 41.04 54.405 ;
     RECT  2.16 54.675 41.04 54.945 ;
     RECT  2.16 55.215 41.04 55.485 ;
     RECT  2.16 55.755 41.04 56.025 ;
     RECT  2.16 56.295 41.04 56.565 ;
     RECT  2.16 56.835 41.04 57.105 ;
     RECT  2.16 57.375 41.04 57.645 ;
     RECT  2.16 57.915 41.04 58.185 ;
     RECT  2.16 58.455 41.04 58.725 ;
     RECT  2.16 58.995 41.04 59.265 ;
     RECT  2.16 59.535 41.04 59.805 ;
     RECT  2.16 60.075 41.04 60.345 ;
     RECT  2.16 60.615 41.04 60.885 ;
     RECT  2.16 61.155 41.04 61.425 ;
     RECT  2.16 61.695 41.04 61.965 ;
     RECT  2.16 62.235 41.04 62.505 ;
     RECT  2.16 62.775 41.04 63.045 ;
     RECT  2.16 63.315 41.04 63.585 ;
     RECT  2.16 63.855 41.04 64.125 ;
     RECT  2.16 64.395 41.04 64.665 ;
     RECT  2.16 64.935 41.04 65.205 ;
     RECT  2.16 65.475 41.04 65.745 ;
     RECT  2.16 66.015 41.04 66.285 ;
     RECT  2.16 66.555 41.04 66.825 ;
     RECT  2.16 67.095 41.04 67.365 ;
     RECT  2.16 67.635 41.04 67.905 ;
     RECT  2.16 68.175 41.04 68.445 ;
     RECT  2.16 68.715 41.04 68.985 ;
     RECT  2.16 69.255 41.04 69.525 ;
     RECT  2.16 69.795 41.04 70.065 ;
     RECT  2.16 70.335 41.04 70.605 ;
     RECT  2.16 70.875 41.04 71.145 ;
     RECT  2.16 71.415 41.04 71.685 ;
     RECT  2.16 71.955 41.04 72.225 ;
     RECT  2.16 72.495 41.04 72.765 ;
     RECT  2.16 73.035 41.04 73.305 ;
     RECT  2.16 73.575 41.04 73.845 ;
     RECT  2.16 74.115 41.04 74.385 ;
     RECT  2.16 74.655 41.04 74.925 ;
     RECT  2.16 75.195 41.04 75.465 ;
    LAYER M1 ;
     RECT  2.16 2.151 41.04 75.609 ;
    LAYER M2 ;
     RECT  0.031 35.442 0.139 35.46 ;
     RECT  0.103 38.061 0.139 38.079 ;
     RECT  0.031 34.164 0.175 34.182 ;
     RECT  0.139 36.9 0.175 38.079 ;
     RECT  0.139 39.528 0.175 39.546 ;
     RECT  0.139 40.491 0.175 41.814 ;
     RECT  0.139 35.28 0.211 35.46 ;
     RECT  0.175 39.528 0.211 41.814 ;
     RECT  0.175 44.73 0.247 44.748 ;
     RECT  0.175 33.93 0.355 34.182 ;
     RECT  0.211 35.01 0.355 35.46 ;
     RECT  0.355 33.93 0.463 35.46 ;
     RECT  0.211 39.528 0.491 42.282 ;
     RECT  0.463 33.93 0.535 35.964 ;
     RECT  0.175 36.9 0.535 38.304 ;
     RECT  0.491 39.528 0.535 40.509 ;
     RECT  0.535 39.222 0.599 40.509 ;
     RECT  0.491 41.418 0.607 42.282 ;
     RECT  0.571 43.074 0.607 43.092 ;
     RECT  0.643 43.848 0.823 43.866 ;
     RECT  0.247 44.622 0.823 45.18 ;
     RECT  0.607 41.418 1.175 43.092 ;
     RECT  0.535 33.93 1.427 38.304 ;
     RECT  1.175 41.49 1.759 43.092 ;
     RECT  0.823 43.848 1.759 45.18 ;
     RECT  1.427 33.93 2.16 37.386 ;
     RECT  1.427 38.286 2.16 38.304 ;
     RECT  0.599 39.222 2.16 40.356 ;
     RECT  1.759 41.49 2.16 45.18 ;
     RECT  2.16 2.151 6.799 75.609 ;
     RECT  6.799 2.106 7.763 75.609 ;
     RECT  7.763 2.151 8.959 75.609 ;
     RECT  8.959 2.106 11.183 75.609 ;
     RECT  11.183 2.151 41.04 75.609 ;
     RECT  41.04 40.068 42.179 40.086 ;
    LAYER M3 ;
     RECT  14.004 0.091 14.022 0.139 ;
     RECT  10.944 0.091 11.502 0.235 ;
     RECT  13.932 0.139 14.022 0.283 ;
     RECT  9.72 0.283 9.738 0.461 ;
     RECT  6.264 0.523 6.282 0.571 ;
     RECT  7.956 0.571 8.298 1.147 ;
     RECT  6.264 0.571 6.75 1.627 ;
     RECT  6.264 1.627 7.038 1.675 ;
     RECT  7.956 1.147 8.514 1.675 ;
     RECT  10.944 0.235 12.006 1.723 ;
     RECT  9.72 1.723 12.006 1.771 ;
     RECT  6.264 1.675 8.514 1.819 ;
     RECT  9.72 1.771 12.15 1.819 ;
     RECT  6.264 1.819 12.546 2.143 ;
     RECT  13.932 0.283 14.058 2.143 ;
     RECT  21.636 1.723 21.654 2.143 ;
     RECT  26.715 2.143 26.805 2.191 ;
     RECT  18.615 2.143 18.705 2.227 ;
     RECT  29.415 2.143 29.505 2.251 ;
     RECT  6.264 2.143 14.058 2.263 ;
     RECT  21.315 2.143 21.654 2.263 ;
     RECT  30.492 2.227 30.51 2.263 ;
     RECT  25.272 2.263 25.29 2.335 ;
     RECT  6.264 2.263 14.49 2.371 ;
     RECT  19.764 2.263 19.782 2.371 ;
     RECT  23.076 2.335 23.094 2.371 ;
     RECT  29.415 2.251 29.538 2.371 ;
     RECT  30.492 2.263 30.726 2.371 ;
     RECT  32.115 2.143 32.205 2.371 ;
     RECT  2.415 2.143 2.505 2.413 ;
     RECT  5.115 2.143 5.205 2.413 ;
     RECT  15.915 2.143 16.005 2.413 ;
     RECT  24.015 2.143 24.105 2.413 ;
     RECT  26.244 2.191 26.805 2.413 ;
     RECT  29.415 2.371 32.205 2.413 ;
     RECT  34.815 2.143 34.905 2.413 ;
     RECT  37.515 2.143 37.605 2.413 ;
     RECT  40.215 2.143 40.305 2.413 ;
     RECT  5.115 2.413 5.397 2.461 ;
     RECT  6.228 2.371 14.49 2.461 ;
     RECT  29.415 2.413 32.397 2.461 ;
     RECT  19.764 2.371 20.034 2.497 ;
     RECT  23.076 2.371 23.166 2.497 ;
     RECT  24.015 2.413 24.297 2.497 ;
     RECT  28.656 2.371 28.674 2.497 ;
     RECT  29.415 2.461 32.634 2.497 ;
     RECT  18.615 2.227 18.954 2.533 ;
     RECT  23.076 2.497 24.297 2.533 ;
     RECT  25.236 2.335 25.29 2.533 ;
     RECT  15.915 2.413 16.197 2.569 ;
     RECT  5.115 2.461 5.454 2.605 ;
     RECT  6.192 2.461 14.49 2.605 ;
     RECT  17.316 2.263 17.766 2.605 ;
     RECT  26.244 2.413 26.997 2.605 ;
     RECT  28.656 2.497 32.634 2.605 ;
     RECT  4.932 2.605 5.454 2.641 ;
     RECT  6.192 2.605 15.066 2.641 ;
     RECT  15.915 2.569 16.398 2.641 ;
     RECT  18.576 2.533 18.954 2.641 ;
     RECT  19.764 2.497 20.142 2.641 ;
     RECT  23.076 2.533 25.29 2.641 ;
     RECT  26.244 2.605 27.162 2.641 ;
     RECT  28.656 2.605 32.706 2.641 ;
     RECT  4.896 2.641 16.398 2.731 ;
     RECT  4.896 2.731 16.506 2.767 ;
     RECT  17.316 2.605 17.838 2.767 ;
     RECT  23.076 2.641 27.27 2.767 ;
     RECT  28.476 2.641 32.706 2.767 ;
     RECT  22.428 2.767 27.27 2.875 ;
     RECT  28.116 2.767 32.706 2.875 ;
     RECT  4.032 2.767 4.05 2.911 ;
     RECT  4.896 2.767 17.838 2.911 ;
     RECT  21.276 2.263 21.654 2.911 ;
     RECT  22.428 2.875 32.706 2.911 ;
     RECT  4.032 2.911 17.838 3.073 ;
     RECT  18.576 2.641 20.142 3.073 ;
     RECT  3.672 3.073 20.142 3.181 ;
     RECT  21.276 2.911 32.706 3.181 ;
     RECT  2.415 2.413 2.697 3.259 ;
     RECT  3.42 3.181 32.706 3.259 ;
     RECT  2.415 3.259 32.706 3.335 ;
     RECT  3.42 3.335 32.706 3.343 ;
     RECT  3.42 3.343 32.886 3.605 ;
     RECT  3.456 3.605 32.886 3.649 ;
     RECT  3.456 3.649 33.39 3.839 ;
     RECT  3.6 3.839 33.39 4.225 ;
     RECT  3.6 4.225 33.426 4.261 ;
     RECT  3.6 4.261 33.606 4.379 ;
     RECT  34.815 2.413 35.097 4.531 ;
     RECT  34.452 4.531 35.097 4.721 ;
     RECT  2.415 3.335 2.697 5.161 ;
     RECT  3.6 4.379 33.534 5.161 ;
     RECT  2.415 5.161 33.534 5.701 ;
     RECT  2.415 5.701 33.93 6.421 ;
     RECT  34.815 4.721 35.097 6.421 ;
     RECT  2.415 6.421 35.097 10.939 ;
     RECT  35.856 8.815 35.874 10.939 ;
     RECT  2.415 10.939 35.874 18.031 ;
     RECT  2.412 18.031 35.874 18.221 ;
     RECT  2.415 18.221 35.874 18.995 ;
     RECT  2.415 18.995 19.53 19.229 ;
     RECT  2.415 19.229 19.494 19.322 ;
     RECT  20.268 18.995 35.874 19.499 ;
     RECT  2.34 19.322 19.494 20.107 ;
     RECT  20.268 19.499 35.55 20.107 ;
     RECT  2.34 20.107 35.55 20.453 ;
     RECT  2.415 20.453 35.55 21.271 ;
     RECT  2.415 21.271 35.73 21.533 ;
     RECT  2.415 21.533 35.55 22.279 ;
     RECT  2.415 22.279 35.802 22.585 ;
     RECT  2.415 22.585 36.126 22.843 ;
     RECT  2.415 22.843 36.198 23.161 ;
     RECT  2.415 23.161 36.306 23.323 ;
     RECT  2.415 23.323 36.378 23.729 ;
     RECT  2.415 23.729 36.126 24.475 ;
     RECT  40.215 2.413 40.497 24.781 ;
     RECT  39.924 24.781 40.497 24.899 ;
     RECT  38.952 24.979 38.97 25.015 ;
     RECT  37.515 2.413 37.797 25.051 ;
     RECT  38.952 25.015 39.438 25.051 ;
     RECT  37.515 25.051 37.962 25.177 ;
     RECT  38.808 25.051 39.438 25.177 ;
     RECT  2.415 24.475 36.522 25.717 ;
     RECT  37.515 25.177 39.438 25.717 ;
     RECT  2.415 25.717 36.558 25.753 ;
     RECT  37.296 25.717 39.438 25.753 ;
     RECT  2.415 25.753 39.438 26.941 ;
     RECT  40.215 24.899 40.497 26.941 ;
     RECT  2.415 26.941 40.497 27.059 ;
     RECT  2.415 27.059 39.438 27.949 ;
     RECT  40.215 27.059 40.497 27.949 ;
     RECT  2.415 27.949 40.497 30.883 ;
     RECT  2.376 30.883 40.497 31.339 ;
     RECT  2.304 31.339 40.497 31.919 ;
     RECT  2.376 31.919 40.497 33.575 ;
     RECT  0.18 33.925 0.198 34.087 ;
     RECT  0.18 34.087 0.27 34.123 ;
     RECT  0.18 34.123 0.306 34.159 ;
     RECT  0.036 34.159 0.306 34.393 ;
     RECT  2.415 33.575 40.497 34.465 ;
     RECT  0.036 34.393 0.378 35.465 ;
     RECT  0.144 35.465 0.378 35.545 ;
     RECT  0.144 35.545 0.522 35.815 ;
     RECT  0.144 35.815 0.558 35.933 ;
     RECT  2.304 34.465 40.497 36.085 ;
     RECT  0.252 35.933 0.558 36.283 ;
     RECT  0.252 36.283 1.278 36.355 ;
     RECT  0.252 36.355 1.386 36.413 ;
     RECT  2.268 36.085 40.497 36.481 ;
     RECT  0.252 36.413 1.17 36.653 ;
     RECT  0.252 36.653 0.558 36.811 ;
     RECT  2.232 36.481 40.497 37.049 ;
     RECT  0.144 36.811 0.558 37.819 ;
     RECT  2.304 37.049 40.497 37.819 ;
     RECT  2.232 37.819 40.497 37.859 ;
     RECT  0.144 37.819 1.17 37.867 ;
     RECT  0.144 37.867 1.386 37.975 ;
     RECT  0.144 37.975 1.422 38.045 ;
     RECT  0.144 38.045 0.414 38.056 ;
     RECT  0.108 38.056 0.414 38.084 ;
     RECT  0.108 38.084 0.306 38.093 ;
     RECT  1.152 38.045 1.422 38.093 ;
     RECT  0.144 38.093 0.306 38.189 ;
     RECT  1.152 38.093 1.314 38.189 ;
     RECT  43.092 38.203 43.11 38.381 ;
     RECT  0.144 38.189 0.234 38.477 ;
     RECT  2.304 37.859 40.497 38.515 ;
     RECT  0.216 38.477 0.234 38.525 ;
     RECT  2.304 38.515 40.914 38.669 ;
     RECT  0.54 39.217 0.558 39.403 ;
     RECT  2.304 38.669 40.842 39.451 ;
     RECT  2.268 39.451 40.842 39.488 ;
     RECT  0.324 39.403 0.558 39.499 ;
     RECT  0.144 39.499 0.558 39.547 ;
     RECT  1.296 38.189 1.314 39.547 ;
     RECT  2.304 39.488 40.842 40.019 ;
     RECT  42.156 39.355 42.174 40.091 ;
     RECT  0.144 39.547 1.314 40.361 ;
     RECT  0.144 40.361 1.278 41.323 ;
     RECT  2.304 40.019 40.497 41.323 ;
     RECT  0.144 41.323 40.497 41.819 ;
     RECT  0.18 41.819 40.497 43.979 ;
     RECT  1.152 43.979 40.497 44.105 ;
     RECT  1.8 44.105 40.497 44.447 ;
     RECT  2.376 44.447 40.497 44.609 ;
     RECT  0.18 43.979 0.342 44.717 ;
     RECT  0.18 44.717 0.27 44.753 ;
     RECT  0.252 44.753 0.27 45.185 ;
     RECT  2.415 44.609 40.497 45.329 ;
     RECT  2.415 45.329 39.438 45.725 ;
     RECT  2.415 45.725 39.402 46.841 ;
     RECT  2.415 46.841 39.33 47.047 ;
     RECT  2.412 47.047 39.33 47.117 ;
     RECT  2.415 47.117 39.33 47.579 ;
     RECT  2.415 47.579 39.294 48.631 ;
     RECT  2.376 48.631 39.294 49.541 ;
     RECT  2.376 49.541 39.15 50.431 ;
     RECT  2.376 50.431 39.258 50.693 ;
     RECT  2.376 50.693 39.114 51.359 ;
     RECT  2.376 51.359 38.97 51.395 ;
     RECT  2.376 51.395 38.826 51.467 ;
     RECT  2.376 51.467 38.466 51.539 ;
     RECT  2.376 51.539 38.43 51.773 ;
     RECT  31.644 51.773 37.89 52.169 ;
     RECT  2.376 51.773 30.906 52.709 ;
     RECT  31.644 52.169 37.854 52.979 ;
     RECT  2.415 52.709 30.906 53.023 ;
     RECT  31.644 52.979 37.797 53.023 ;
     RECT  2.415 53.023 37.797 54.203 ;
     RECT  31.68 54.203 37.797 54.365 ;
     RECT  31.968 54.365 37.797 54.401 ;
     RECT  31.968 54.401 36.738 54.635 ;
     RECT  2.415 54.203 30.87 55.255 ;
     RECT  31.968 54.635 36.702 55.255 ;
     RECT  2.415 55.255 36.702 55.409 ;
     RECT  2.415 55.409 36.594 55.525 ;
     RECT  2.376 55.525 36.594 55.715 ;
     RECT  2.415 55.715 36.594 56.759 ;
     RECT  2.415 56.759 36.45 57.451 ;
     RECT  2.376 57.451 36.45 57.839 ;
     RECT  2.376 57.839 35.586 57.983 ;
     RECT  36.432 57.839 36.45 58.109 ;
     RECT  2.376 57.983 35.55 58.181 ;
     RECT  2.376 58.181 35.514 58.685 ;
     RECT  2.415 58.685 35.514 59.851 ;
     RECT  2.376 59.851 35.514 60.539 ;
     RECT  2.415 60.539 35.514 62.429 ;
     RECT  2.415 62.429 19.17 62.545 ;
     RECT  2.376 62.545 19.17 62.699 ;
     RECT  2.415 62.699 18.897 62.765 ;
     RECT  20.196 62.429 35.514 62.807 ;
     RECT  14.22 62.765 18.897 63.239 ;
     RECT  14.472 63.239 17.442 63.248 ;
     RECT  14.832 63.248 17.442 63.419 ;
     RECT  15.048 63.419 17.442 63.509 ;
     RECT  15.048 63.509 17.37 63.545 ;
     RECT  20.484 62.807 35.514 63.589 ;
     RECT  2.415 62.765 13.497 63.653 ;
     RECT  20.448 63.589 35.514 63.779 ;
     RECT  15.3 63.545 17.37 63.815 ;
     RECT  20.484 63.779 35.514 63.815 ;
     RECT  11.916 63.653 13.497 63.851 ;
     RECT  2.415 63.653 10.998 63.883 ;
     RECT  2.376 63.883 10.998 64.049 ;
     RECT  11.916 63.851 12.078 64.049 ;
     RECT  15.3 63.815 16.29 64.049 ;
     RECT  20.52 63.815 35.514 64.049 ;
     RECT  11.916 64.049 12.042 64.085 ;
     RECT  12.924 63.851 13.497 64.085 ;
     RECT  15.3 64.049 16.197 64.085 ;
     RECT  17.208 63.815 17.37 64.085 ;
     RECT  11.988 64.085 12.042 64.319 ;
     RECT  17.28 64.085 17.37 64.319 ;
     RECT  12.96 64.085 13.497 64.355 ;
     RECT  12.024 64.319 12.042 64.391 ;
     RECT  2.415 64.049 10.998 64.661 ;
     RECT  20.592 64.049 35.514 64.733 ;
     RECT  2.415 64.661 10.797 64.903 ;
     RECT  2.34 64.903 10.797 64.973 ;
     RECT  20.664 64.733 35.514 65.129 ;
     RECT  21.132 65.129 35.514 65.507 ;
     RECT  2.415 64.973 10.797 66.763 ;
     RECT  21.168 65.507 35.514 68.675 ;
     RECT  2.376 66.763 10.797 68.783 ;
     RECT  2.376 68.783 9.594 68.909 ;
     RECT  21.312 68.675 35.514 68.945 ;
     RECT  2.376 68.909 9.558 68.968 ;
     RECT  21.315 68.945 35.514 68.981 ;
     RECT  2.415 68.968 9.558 69.017 ;
     RECT  2.415 69.017 9.45 69.179 ;
     RECT  4.968 69.179 9.45 69.251 ;
     RECT  2.415 69.179 4.05 69.449 ;
     RECT  3.672 69.449 4.05 69.485 ;
     RECT  22.824 68.981 35.514 69.529 ;
     RECT  2.415 69.449 2.826 69.719 ;
     RECT  3.672 69.485 3.762 69.719 ;
     RECT  22.824 69.529 35.586 69.719 ;
     RECT  22.824 69.719 35.406 70.259 ;
     RECT  22.824 70.259 35.37 70.303 ;
     RECT  22.788 70.303 35.37 70.529 ;
     RECT  5.115 69.251 9.45 70.943 ;
     RECT  6.48 70.943 9.45 70.951 ;
     RECT  6.48 70.951 9.558 71.141 ;
     RECT  22.824 70.529 35.37 71.339 ;
     RECT  6.48 71.141 9.09 71.362 ;
     RECT  6.84 71.362 9.09 71.375 ;
     RECT  6.84 71.375 8.982 71.609 ;
     RECT  6.84 71.609 6.858 71.645 ;
     RECT  7.596 71.609 8.982 71.753 ;
     RECT  8.964 71.753 8.982 71.879 ;
     RECT  23.112 71.339 35.097 71.987 ;
     RECT  7.596 71.753 8.19 72.149 ;
     RECT  7.596 72.149 8.097 72.185 ;
     RECT  23.256 71.987 35.097 72.221 ;
     RECT  23.364 72.221 35.097 73.031 ;
     RECT  23.364 73.031 33.93 73.139 ;
     RECT  23.364 73.139 31.158 73.273 ;
     RECT  31.896 73.139 33.93 73.337 ;
     RECT  23.328 73.273 31.158 73.381 ;
     RECT  23.148 73.381 31.158 73.543 ;
     RECT  22.824 73.543 31.158 73.769 ;
     RECT  33.264 73.337 33.93 73.769 ;
     RECT  23.04 73.769 31.158 73.841 ;
     RECT  23.256 73.841 31.158 73.877 ;
     RECT  23.508 73.877 31.158 73.921 ;
     RECT  31.896 73.337 32.454 73.921 ;
     RECT  23.508 73.921 32.454 74.039 ;
     RECT  23.508 74.039 30.618 74.075 ;
     RECT  31.896 74.039 32.454 74.075 ;
     RECT  32.076 74.075 32.454 74.083 ;
     RECT  23.544 74.075 30.618 74.147 ;
     RECT  32.076 74.083 33.03 74.147 ;
     RECT  23.868 74.147 30.474 74.309 ;
     RECT  33.912 73.769 33.93 74.309 ;
     RECT  32.115 74.147 33.03 74.345 ;
     RECT  23.868 74.309 30.006 74.381 ;
     RECT  32.115 74.345 32.778 74.381 ;
     RECT  23.868 74.381 24.534 74.417 ;
     RECT  25.272 74.381 29.697 74.417 ;
     RECT  25.632 74.417 29.697 74.453 ;
     RECT  26.244 74.453 29.697 74.477 ;
     RECT  23.868 74.417 24.297 74.489 ;
     RECT  26.244 74.477 28.098 74.489 ;
     RECT  26.244 74.489 27.882 74.579 ;
     RECT  28.872 74.477 29.697 74.651 ;
     RECT  26.244 74.579 27.846 74.687 ;
     RECT  26.715 74.687 27.846 74.849 ;
     RECT  26.715 74.849 27.486 74.957 ;
     RECT  2.415 69.719 2.697 75.347 ;
     RECT  5.115 70.943 5.397 75.347 ;
     RECT  7.815 72.185 8.097 75.347 ;
     RECT  10.515 68.783 10.797 75.347 ;
     RECT  13.215 64.355 13.497 75.347 ;
     RECT  15.915 64.085 16.197 75.347 ;
     RECT  18.615 63.239 18.897 75.347 ;
     RECT  21.315 68.981 21.597 75.347 ;
     RECT  24.015 74.489 24.297 75.347 ;
     RECT  26.715 74.957 26.997 75.347 ;
     RECT  29.415 74.651 29.697 75.347 ;
     RECT  32.115 74.381 32.397 75.347 ;
     RECT  34.815 73.031 35.097 75.347 ;
     RECT  37.515 54.401 37.797 75.347 ;
     RECT  40.215 45.329 40.497 75.347 ;
     RECT  2.415 75.347 2.505 75.617 ;
     RECT  5.115 75.347 5.205 75.617 ;
     RECT  7.815 75.347 7.905 75.617 ;
     RECT  10.515 75.347 10.605 75.617 ;
     RECT  13.215 75.347 13.305 75.617 ;
     RECT  15.915 75.347 16.005 75.617 ;
     RECT  18.615 75.347 18.705 75.617 ;
     RECT  21.315 75.347 21.405 75.617 ;
     RECT  24.015 75.347 24.105 75.617 ;
     RECT  26.715 75.347 26.805 75.617 ;
     RECT  29.415 75.347 29.505 75.617 ;
     RECT  32.115 75.347 32.205 75.617 ;
     RECT  34.815 75.347 34.905 75.617 ;
     RECT  37.515 75.347 37.605 75.617 ;
     RECT  40.215 75.347 40.305 75.617 ;
    LAYER M4 ;
     RECT  0.06 35.376 0.133 38.376 ;
     RECT  0.06 39.36 0.133 42.36 ;
     RECT  0.133 35.28 0.181 42.408 ;
     RECT  0.181 35.184 0.229 42.408 ;
     RECT  0.229 34.944 0.317 42.408 ;
     RECT  0.229 43.824 2.293 43.848 ;
     RECT  2.252 31.344 2.365 31.368 ;
     RECT  2.293 18.192 2.408 18.216 ;
     RECT  2.265 19.344 2.408 19.368 ;
     RECT  2.293 27.6 2.408 27.624 ;
     RECT  2.365 31.344 2.408 31.8 ;
     RECT  2.365 32.784 2.408 32.808 ;
     RECT  0.317 34.944 2.408 42.36 ;
     RECT  2.293 43.344 2.408 43.848 ;
     RECT  2.401 47.088 2.408 47.112 ;
     RECT  2.365 57.6 2.408 57.624 ;
     RECT  2.293 58.656 2.408 58.68 ;
     RECT  2.293 59.856 2.408 59.88 ;
     RECT  2.365 63.888 2.408 63.912 ;
     RECT  2.293 64.944 2.408 64.968 ;
     RECT  2.293 66.768 2.408 66.792 ;
     RECT  2.365 68.928 2.408 68.952 ;
     RECT  2.408 2.148 2.512 75.612 ;
     RECT  2.512 2.418 2.704 75.342 ;
     RECT  2.704 29.088 2.819 49.512 ;
     RECT  2.704 6.816 2.867 7.944 ;
     RECT  2.704 66.576 2.867 69.672 ;
     RECT  2.867 7.584 2.873 7.944 ;
     RECT  2.704 13.824 2.873 14.952 ;
     RECT  2.704 56.976 2.909 57.624 ;
     RECT  2.819 29.088 2.963 47.88 ;
     RECT  2.963 29.088 3.089 45.72 ;
     RECT  2.963 46.752 3.089 47.88 ;
     RECT  2.704 26.448 3.107 27.96 ;
     RECT  2.867 66.576 3.107 69.48 ;
     RECT  2.704 25.296 3.148 25.32 ;
     RECT  2.704 22.752 3.347 22.824 ;
     RECT  2.704 21.552 3.388 21.576 ;
     RECT  3.107 67.824 3.436 69.48 ;
     RECT  2.704 60.384 3.601 61.32 ;
     RECT  3.601 61.296 3.628 61.32 ;
     RECT  3.089 32.784 3.629 45.72 ;
     RECT  2.704 59.28 3.673 59.304 ;
     RECT  2.704 16.416 3.683 16.824 ;
     RECT  2.873 13.824 3.697 13.848 ;
     RECT  2.704 50.592 3.697 50.616 ;
     RECT  3.436 67.824 3.737 67.848 ;
     RECT  2.704 62.544 3.809 62.664 ;
     RECT  3.697 13.104 3.836 13.848 ;
     RECT  2.873 14.928 3.836 14.952 ;
     RECT  2.704 53.568 3.877 53.592 ;
     RECT  3.836 13.104 3.923 14.952 ;
     RECT  3.436 69.36 3.923 69.48 ;
     RECT  3.923 14.784 3.925 14.952 ;
     RECT  2.819 49.008 3.949 49.512 ;
     RECT  3.697 50.496 3.949 50.616 ;
     RECT  3.925 14.784 3.971 15.48 ;
     RECT  3.949 49.008 3.98 50.616 ;
     RECT  2.909 56.976 3.985 57 ;
     RECT  2.704 3.264 4.021 3.288 ;
     RECT  3.985 56.976 4.025 57.336 ;
     RECT  3.98 48.912 4.057 50.616 ;
     RECT  3.949 51.648 4.057 51.672 ;
     RECT  3.089 46.752 4.085 47.352 ;
     RECT  4.057 48.48 4.085 51.672 ;
     RECT  3.089 29.088 4.093 31.8 ;
     RECT  3.629 32.784 4.093 45.24 ;
     RECT  4.021 2.832 4.105 3.288 ;
     RECT  2.873 7.584 4.129 7.608 ;
     RECT  3.877 53.232 4.129 53.592 ;
     RECT  3.107 66.576 4.129 66.696 ;
     RECT  4.085 46.752 4.133 51.672 ;
     RECT  3.107 27.6 4.201 27.96 ;
     RECT  4.129 53.232 4.201 54.36 ;
     RECT  2.704 63.84 4.22 63.912 ;
     RECT  2.704 64.896 4.22 65.016 ;
     RECT  4.201 27.456 4.273 27.96 ;
     RECT  4.129 7.584 4.309 7.992 ;
     RECT  2.704 11.952 4.309 11.976 ;
     RECT  4.133 46.752 4.316 51.432 ;
     RECT  4.273 24.384 4.345 24.408 ;
     RECT  2.704 10.848 4.453 10.92 ;
     RECT  4.309 11.904 4.453 11.976 ;
     RECT  4.273 26.784 4.453 27.96 ;
     RECT  4.453 26.736 4.597 27.96 ;
     RECT  4.093 29.088 4.597 45.24 ;
     RECT  4.316 46.464 4.597 51.432 ;
     RECT  3.809 62.544 4.633 62.568 ;
     RECT  4.453 10.848 4.669 11.976 ;
     RECT  3.923 13.104 4.669 13.128 ;
     RECT  4.597 26.352 4.796 27.96 ;
     RECT  4.597 29.088 4.796 51.432 ;
     RECT  3.971 14.928 4.837 15.48 ;
     RECT  3.683 16.512 4.837 16.824 ;
     RECT  4.345 24.384 4.837 25.08 ;
     RECT  4.777 60.336 4.849 60.36 ;
     RECT  4.669 10.848 4.885 13.128 ;
     RECT  4.633 21.696 4.885 21.72 ;
     RECT  3.347 22.752 4.885 22.776 ;
     RECT  4.025 57.312 4.885 57.336 ;
     RECT  4.633 62.304 4.921 62.568 ;
     RECT  2.704 19.344 4.933 19.368 ;
     RECT  4.796 26.352 4.933 51.432 ;
     RECT  4.837 14.928 4.957 16.824 ;
     RECT  4.021 5.712 4.981 5.736 ;
     RECT  4.309 6.864 4.981 7.992 ;
     RECT  4.933 8.976 4.981 9 ;
     RECT  4.22 63.84 5.029 65.016 ;
     RECT  4.129 66.48 5.029 66.696 ;
     RECT  4.981 4.752 5.065 5.736 ;
     RECT  4.957 14.928 5.065 17.112 ;
     RECT  4.201 53.232 5.065 54.408 ;
     RECT  4.417 55.68 5.065 55.704 ;
     RECT  4.105 3.264 5.108 3.288 ;
     RECT  5.065 4.752 5.108 5.832 ;
     RECT  4.981 6.864 5.108 9 ;
     RECT  4.885 10.032 5.108 13.128 ;
     RECT  5.065 14.112 5.108 17.112 ;
     RECT  4.933 18.768 5.108 20.136 ;
     RECT  4.885 21.696 5.108 22.776 ;
     RECT  4.837 24.144 5.108 25.08 ;
     RECT  4.933 26.256 5.108 51.432 ;
     RECT  5.065 53.232 5.108 55.704 ;
     RECT  4.885 57.312 5.108 58.008 ;
     RECT  4.849 60.096 5.108 60.36 ;
     RECT  4.921 62.304 5.108 62.664 ;
     RECT  5.029 63.84 5.108 66.696 ;
     RECT  4.633 68.496 5.108 68.952 ;
     RECT  3.877 70.656 5.108 70.68 ;
     RECT  5.108 2.148 5.212 75.612 ;
     RECT  5.212 2.418 5.404 75.342 ;
     RECT  5.404 7.344 5.465 9 ;
     RECT  5.404 59.808 5.465 62.76 ;
     RECT  5.404 57.312 5.501 58.584 ;
     RECT  5.404 23.184 5.555 52.44 ;
     RECT  5.404 12.96 5.603 20.328 ;
     RECT  5.555 23.184 5.603 50.28 ;
     RECT  5.603 12.96 5.644 15.48 ;
     RECT  5.603 16.8 5.681 20.328 ;
     RECT  5.603 23.184 5.699 24.6 ;
     RECT  5.404 10.368 5.789 10.728 ;
     RECT  5.404 66.48 5.789 66.792 ;
     RECT  5.404 53.52 6.041 55.704 ;
     RECT  5.404 64.128 6.041 65.016 ;
     RECT  5.789 10.368 6.185 10.632 ;
     RECT  5.681 16.8 6.185 18.792 ;
     RECT  6.185 18.768 6.275 18.792 ;
     RECT  6.041 64.128 6.293 64.92 ;
     RECT  5.465 59.808 6.323 62.568 ;
     RECT  5.644 14.112 6.329 15.48 ;
     RECT  5.603 25.632 6.364 50.28 ;
     RECT  5.555 51.264 6.373 52.44 ;
     RECT  5.404 2.832 6.389 2.856 ;
     RECT  6.389 2.304 6.397 2.856 ;
     RECT  6.041 53.52 6.397 54.12 ;
     RECT  6.041 55.152 6.397 55.704 ;
     RECT  6.185 10.368 6.428 10.44 ;
     RECT  5.404 70.656 6.428 70.68 ;
     RECT  6.373 51.264 6.469 52.488 ;
     RECT  6.397 53.472 6.469 54.12 ;
     RECT  5.404 68.64 6.469 69.24 ;
     RECT  6.428 70.656 6.469 71.064 ;
     RECT  5.404 5.808 6.505 5.832 ;
     RECT  6.469 70.656 6.515 71.352 ;
     RECT  5.404 21.936 6.517 21.96 ;
     RECT  6.253 0.528 6.563 0.552 ;
     RECT  5.465 7.344 6.613 8.232 ;
     RECT  6.323 59.808 6.617 61.176 ;
     RECT  5.644 12.96 6.653 12.984 ;
     RECT  5.501 57.312 6.661 57.336 ;
     RECT  6.505 5.28 6.685 5.832 ;
     RECT  6.329 14.208 6.721 15.48 ;
     RECT  6.185 16.8 6.721 17.496 ;
     RECT  6.517 21.504 6.721 21.96 ;
     RECT  5.699 23.184 6.721 23.928 ;
     RECT  6.721 14.208 6.725 17.496 ;
     RECT  6.428 9.6 6.761 10.44 ;
     RECT  6.364 25.632 6.761 29.112 ;
     RECT  6.364 30.288 6.764 50.28 ;
     RECT  6.469 51.264 6.764 54.12 ;
     RECT  5.681 19.872 6.793 20.328 ;
     RECT  6.761 25.632 6.805 29.064 ;
     RECT  6.515 71.328 6.829 71.352 ;
     RECT  6.397 2.208 6.865 2.856 ;
     RECT  6.793 19.776 6.865 20.328 ;
     RECT  6.397 55.152 6.997 55.8 ;
     RECT  6.865 2.208 7.009 3.144 ;
     RECT  6.613 7.344 7.045 8.52 ;
     RECT  6.761 9.6 7.045 9.912 ;
     RECT  6.661 56.88 7.045 57.336 ;
     RECT  5.501 58.56 7.045 58.584 ;
     RECT  6.721 21.504 7.117 23.928 ;
     RECT  6.323 62.16 7.189 62.568 ;
     RECT  6.685 4.56 7.225 5.832 ;
     RECT  6.997 55.152 7.333 55.896 ;
     RECT  7.045 56.88 7.333 58.584 ;
     RECT  7.189 62.16 7.333 63.48 ;
     RECT  6.764 30.288 7.34 54.12 ;
     RECT  7.333 55.152 7.34 58.584 ;
     RECT  5.789 66.768 7.369 66.792 ;
     RECT  6.469 67.824 7.369 69.24 ;
     RECT  7.225 4.56 7.429 6.264 ;
     RECT  7.045 7.344 7.429 9.912 ;
     RECT  6.617 59.808 7.436 59.832 ;
     RECT  7.009 1.632 7.541 3.144 ;
     RECT  7.429 4.56 7.541 9.912 ;
     RECT  7.369 66.768 7.549 69.864 ;
     RECT  6.829 71.328 7.549 71.64 ;
     RECT  6.617 61.104 7.58 61.176 ;
     RECT  7.333 62.16 7.58 64.44 ;
     RECT  6.677 0.576 7.621 0.6 ;
     RECT  6.725 14.208 7.669 17.112 ;
     RECT  7.292 12.912 7.729 12.936 ;
     RECT  7.405 18.144 7.801 18.168 ;
     RECT  7.541 1.632 7.808 9.912 ;
     RECT  7.369 11.232 7.808 11.256 ;
     RECT  7.729 12.912 7.808 13.08 ;
     RECT  7.669 14.112 7.808 17.112 ;
     RECT  7.801 18.144 7.808 18.264 ;
     RECT  6.865 19.584 7.808 20.328 ;
     RECT  7.117 21.504 7.808 23.976 ;
     RECT  6.805 25.584 7.808 29.064 ;
     RECT  7.34 30.288 7.808 58.584 ;
     RECT  7.436 59.664 7.808 59.832 ;
     RECT  7.58 61.104 7.808 64.44 ;
     RECT  7.549 66.768 7.808 71.64 ;
     RECT  7.808 1.632 7.912 75.612 ;
     RECT  7.621 0.144 7.957 0.6 ;
     RECT  7.912 1.632 7.957 75.342 ;
     RECT  7.957 0.144 8.104 75.342 ;
     RECT  8.104 11.232 8.165 14.136 ;
     RECT  8.104 64.944 8.243 66.264 ;
     RECT  8.104 67.248 8.243 68.616 ;
     RECT  8.104 60.48 8.245 63 ;
     RECT  8.104 28.944 8.273 28.968 ;
     RECT  8.104 0.144 8.309 10.008 ;
     RECT  8.104 30.048 8.339 59.208 ;
     RECT  8.243 67.248 8.345 67.272 ;
     RECT  8.104 26.832 8.381 27.192 ;
     RECT  8.339 30.048 8.387 54.648 ;
     RECT  8.309 1.152 8.425 10.008 ;
     RECT  8.245 60.48 8.435 61.224 ;
     RECT  8.165 11.664 8.453 14.136 ;
     RECT  8.104 25.104 8.489 25.752 ;
     RECT  8.425 1.152 8.525 5.88 ;
     RECT  8.104 20.592 8.525 23.88 ;
     RECT  8.525 21.648 8.597 23.88 ;
     RECT  8.339 55.776 8.669 59.208 ;
     RECT  8.489 25.104 8.705 25.656 ;
     RECT  8.387 30.048 8.705 53.928 ;
     RECT  8.104 17.232 8.813 17.256 ;
     RECT  8.705 52.416 8.813 53.928 ;
     RECT  8.243 68.352 8.849 68.376 ;
     RECT  8.705 25.632 8.867 25.656 ;
     RECT  8.381 27.168 8.885 27.192 ;
     RECT  8.104 18.432 8.921 18.84 ;
     RECT  8.425 6.864 9.065 10.008 ;
     RECT  8.525 20.592 9.065 20.616 ;
     RECT  8.669 56.208 9.065 59.208 ;
     RECT  8.525 1.728 9.107 5.88 ;
     RECT  8.104 15.264 9.133 15.288 ;
     RECT  8.597 21.648 9.137 23.688 ;
     RECT  8.453 11.664 9.205 13.08 ;
     RECT  9.133 15.216 9.277 15.288 ;
     RECT  8.921 18.432 9.301 18.552 ;
     RECT  9.097 28.464 9.301 28.488 ;
     RECT  9.301 27.312 9.349 28.488 ;
     RECT  9.137 21.648 9.353 23.4 ;
     RECT  9.301 17.616 9.388 18.552 ;
     RECT  9.065 7.632 9.421 10.008 ;
     RECT  8.435 60.576 9.421 61.224 ;
     RECT  8.245 62.496 9.421 63 ;
     RECT  9.349 27.312 9.445 28.824 ;
     RECT  8.705 30.048 9.445 51.384 ;
     RECT  8.243 65.616 9.445 65.832 ;
     RECT  9.445 65.136 9.533 65.832 ;
     RECT  8.309 0.144 9.589 0.168 ;
     RECT  9.065 58.848 9.637 59.208 ;
     RECT  9.589 0.144 9.692 0.36 ;
     RECT  9.353 21.648 9.745 21.768 ;
     RECT  9.692 0.144 9.779 0.456 ;
     RECT  9.779 0.144 9.781 0.36 ;
     RECT  9.107 3.408 9.781 5.88 ;
     RECT  8.813 52.8 9.781 53.928 ;
     RECT  9.065 56.208 9.781 57.144 ;
     RECT  9.205 11.376 9.817 13.08 ;
     RECT  8.453 14.112 9.817 14.136 ;
     RECT  9.277 15.216 9.817 15.624 ;
     RECT  9.781 52.8 9.853 57.144 ;
     RECT  9.421 60.576 9.853 63 ;
     RECT  9.493 64.032 9.853 64.056 ;
     RECT  9.853 60.576 9.889 64.056 ;
     RECT  9.388 18.24 9.98 18.552 ;
     RECT  9.98 18.24 10.021 18.792 ;
     RECT  9.445 27.312 10.033 51.384 ;
     RECT  9.853 52.704 10.033 57.144 ;
     RECT  9.781 3.408 10.069 6.312 ;
     RECT  10.033 27.312 10.069 57.144 ;
     RECT  9.421 7.632 10.177 10.056 ;
     RECT  10.069 2.88 10.249 6.312 ;
     RECT  9.637 58.848 10.249 59.304 ;
     RECT  9.889 60.288 10.249 64.056 ;
     RECT  9.817 15.216 10.261 16.536 ;
     RECT  10.069 27.072 10.285 57.144 ;
     RECT  9.107 1.728 10.309 1.848 ;
     RECT  10.249 2.88 10.309 6.36 ;
     RECT  9.745 20.832 10.465 21.768 ;
     RECT  9.353 23.376 10.465 23.4 ;
     RECT  10.309 1.728 10.508 6.36 ;
     RECT  10.177 7.344 10.508 10.056 ;
     RECT  9.817 11.376 10.508 14.136 ;
     RECT  10.261 15.216 10.508 16.68 ;
     RECT  10.021 18.24 10.508 19.416 ;
     RECT  10.465 20.832 10.508 23.4 ;
     RECT  10.141 25.632 10.508 25.656 ;
     RECT  10.285 26.736 10.508 57.144 ;
     RECT  10.249 58.848 10.508 64.056 ;
     RECT  9.533 65.568 10.508 65.832 ;
     RECT  9.277 68.88 10.508 68.904 ;
     RECT  10.508 1.728 10.612 75.612 ;
     RECT  10.612 1.728 10.729 75.342 ;
     RECT  9.781 0.096 10.741 0.36 ;
     RECT  10.729 2.016 10.804 75.342 ;
     RECT  10.804 60 10.829 64.056 ;
     RECT  10.804 28.272 10.931 52.824 ;
     RECT  10.804 21.552 10.972 25.032 ;
     RECT  10.829 60.576 10.973 64.056 ;
     RECT  10.804 2.016 10.979 4.056 ;
     RECT  10.804 53.904 11.081 55.8 ;
     RECT  10.804 5.136 11.189 12.024 ;
     RECT  10.804 27.072 11.189 27.096 ;
     RECT  10.804 58.128 11.219 58.68 ;
     RECT  10.931 28.272 11.411 31.464 ;
     RECT  11.081 53.904 11.411 54.888 ;
     RECT  10.973 60.576 11.441 62.712 ;
     RECT  11.189 5.136 11.459 11.544 ;
     RECT  10.804 19.344 11.459 20.088 ;
     RECT  10.804 56.784 11.485 57.144 ;
     RECT  11.411 28.272 11.507 30.216 ;
     RECT  11.507 28.272 11.549 30.168 ;
     RECT  10.804 15.744 11.621 16.68 ;
     RECT  10.804 18.192 11.729 18.216 ;
     RECT  10.972 21.552 11.729 21.576 ;
     RECT  11.441 61.776 11.747 62.712 ;
     RECT  10.972 22.656 11.789 25.032 ;
     RECT  11.549 28.272 11.801 29.88 ;
     RECT  11.801 28.272 11.845 29.352 ;
     RECT  11.797 20.496 11.881 20.52 ;
     RECT  11.789 22.656 11.891 25.512 ;
     RECT  11.485 56.784 11.905 56.856 ;
     RECT  11.441 60.576 11.941 60.696 ;
     RECT  10.973 63.792 11.945 64.056 ;
     RECT  10.979 2.256 11.977 4.056 ;
     RECT  10.931 32.496 11.977 52.824 ;
     RECT  10.741 0.096 11.989 0.6 ;
     RECT  11.977 1.728 11.989 4.056 ;
     RECT  11.459 5.136 11.989 10.296 ;
     RECT  10.804 13.824 12.013 14.712 ;
     RECT  11.459 11.424 12.017 11.544 ;
     RECT  11.411 31.2 12.037 31.464 ;
     RECT  11.977 32.448 12.037 52.824 ;
     RECT  11.411 53.904 12.037 54.744 ;
     RECT  11.219 58.512 12.049 58.68 ;
     RECT  11.459 19.344 12.133 19.416 ;
     RECT  11.845 28.224 12.179 29.352 ;
     RECT  12.133 18.768 12.22 19.416 ;
     RECT  12.049 58.512 12.229 58.776 ;
     RECT  11.891 22.656 12.233 25.032 ;
     RECT  11.869 17.712 12.265 17.736 ;
     RECT  11.621 16.56 12.301 16.68 ;
     RECT  12.265 17.664 12.301 17.736 ;
     RECT  12.233 22.656 12.409 23.112 ;
     RECT  12.157 12.768 12.445 12.792 ;
     RECT  12.013 13.824 12.445 15.384 ;
     RECT  12.445 12.768 12.481 15.384 ;
     RECT  11.905 55.872 12.517 56.856 ;
     RECT  12.229 57.936 12.517 58.776 ;
     RECT  12.013 26.112 12.625 26.136 ;
     RECT  11.989 0.096 12.707 10.296 ;
     RECT  12.481 12.624 12.733 15.384 ;
     RECT  12.707 0.096 12.803 1.176 ;
     RECT  12.733 12.528 12.985 15.384 ;
     RECT  12.037 31.2 12.985 54.744 ;
     RECT  12.517 55.872 12.985 58.776 ;
     RECT  11.941 60.432 13.004 60.696 ;
     RECT  11.747 62.496 13.045 62.712 ;
     RECT  12.707 2.148 13.093 10.296 ;
     RECT  12.017 11.424 13.093 11.448 ;
     RECT  12.301 16.56 13.093 17.736 ;
     RECT  12.22 19.344 13.093 19.416 ;
     RECT  13.004 60.096 13.093 60.696 ;
     RECT  13.093 2.148 13.129 11.448 ;
     RECT  12.409 22.032 13.201 23.112 ;
     RECT  13.129 2.148 13.208 11.544 ;
     RECT  12.985 12.528 13.208 15.48 ;
     RECT  13.093 16.56 13.208 17.928 ;
     RECT  13.093 19.344 13.208 20.184 ;
     RECT  13.201 22.032 13.208 23.304 ;
     RECT  12.233 24.48 13.208 25.032 ;
     RECT  12.625 26.112 13.208 26.76 ;
     RECT  12.179 28.224 13.208 28.488 ;
     RECT  12.769 29.808 13.208 29.832 ;
     RECT  12.985 31.2 13.208 58.776 ;
     RECT  13.093 59.808 13.208 60.84 ;
     RECT  13.045 62.496 13.208 62.76 ;
     RECT  11.945 63.792 13.208 63.816 ;
     RECT  13.208 2.148 13.312 75.612 ;
     RECT  13.312 2.418 13.504 75.342 ;
     RECT  13.504 19.344 13.601 23.304 ;
     RECT  13.504 3.408 13.619 10.152 ;
     RECT  13.504 48.144 13.619 55.896 ;
     RECT  13.601 20.16 13.637 23.304 ;
     RECT  13.504 31.872 13.637 46.92 ;
     RECT  13.619 51.264 13.645 55.896 ;
     RECT  13.619 3.408 13.667 3.432 ;
     RECT  13.504 60.816 13.667 63.24 ;
     RECT  13.504 13.056 13.673 18.072 ;
     RECT  13.673 17.376 13.709 18.072 ;
     RECT  13.637 31.872 13.709 46.632 ;
     RECT  13.645 51.792 13.763 55.896 ;
     RECT  13.667 61.584 13.781 63.24 ;
     RECT  13.763 51.792 13.804 51.816 ;
     RECT  13.709 31.872 13.825 46.248 ;
     RECT  13.504 27.888 13.853 28.488 ;
     RECT  13.673 13.056 13.997 16.296 ;
     RECT  13.763 52.992 13.997 55.896 ;
     RECT  12.803 0.096 14.033 0.312 ;
     RECT  13.781 62.496 14.033 63.24 ;
     RECT  13.825 32.304 14.051 46.248 ;
     RECT  14.033 0.288 14.069 0.312 ;
     RECT  14.051 32.304 14.105 44.376 ;
     RECT  14.051 45.6 14.185 46.248 ;
     RECT  14.105 38.16 14.321 44.376 ;
     RECT  14.105 32.304 14.387 36.936 ;
     RECT  13.504 24.48 14.497 24.504 ;
     RECT  13.504 25.632 14.497 26.136 ;
     RECT  13.504 57.936 14.531 59.592 ;
     RECT  13.504 11.136 14.537 11.976 ;
     RECT  13.709 17.424 14.569 18.072 ;
     RECT  14.569 17.424 14.609 18.408 ;
     RECT  13.997 16.272 14.627 16.296 ;
     RECT  14.497 24.48 14.645 26.136 ;
     RECT  14.321 38.16 14.681 41.064 ;
     RECT  13.637 20.16 14.713 21.096 ;
     RECT  14.185 46.224 14.749 46.248 ;
     RECT  14.713 20.16 14.821 21.672 ;
     RECT  13.637 22.752 14.821 23.304 ;
     RECT  13.853 27.888 14.821 28.152 ;
     RECT  13.619 48.144 14.821 49.848 ;
     RECT  13.619 4.944 14.825 10.152 ;
     RECT  14.821 20.16 14.861 23.304 ;
     RECT  14.681 40.896 14.861 41.064 ;
     RECT  14.645 24.48 14.905 25.32 ;
     RECT  14.828 3.936 14.915 3.96 ;
     RECT  14.785 52.416 15.061 52.44 ;
     RECT  14.033 62.736 15.061 63.24 ;
     RECT  15.061 62.448 15.073 63.24 ;
     RECT  14.821 48.144 15.109 50.328 ;
     RECT  15.073 61.92 15.181 63.24 ;
     RECT  14.387 32.304 15.217 36.888 ;
     RECT  13.997 53.472 15.217 55.896 ;
     RECT  15.181 61.104 15.217 63.24 ;
     RECT  13.997 13.056 15.253 15.144 ;
     RECT  14.861 22.176 15.253 23.304 ;
     RECT  14.825 4.944 15.289 10.008 ;
     RECT  14.905 24.48 15.325 24.792 ;
     RECT  14.821 26.784 15.325 26.808 ;
     RECT  14.821 27.888 15.325 28.248 ;
     RECT  14.321 42.192 15.469 44.376 ;
     RECT  15.253 12.528 15.589 15.144 ;
     RECT  15.109 48.144 15.637 50.712 ;
     RECT  15.061 51.984 15.637 52.44 ;
     RECT  14.537 11.136 15.649 11.16 ;
     RECT  14.869 2.64 15.685 2.664 ;
     RECT  14.531 57.936 15.757 59.208 ;
     RECT  14.861 41.04 15.793 41.064 ;
     RECT  15.469 42.192 15.793 44.472 ;
     RECT  14.749 46.224 15.793 46.92 ;
     RECT  15.289 4.608 15.901 10.008 ;
     RECT  15.649 11.136 15.901 11.208 ;
     RECT  15.685 2.64 15.908 2.808 ;
     RECT  15.901 4.608 15.908 11.208 ;
     RECT  15.589 12.528 15.908 16.008 ;
     RECT  14.609 17.52 15.908 18.408 ;
     RECT  14.861 20.16 15.908 21.096 ;
     RECT  15.253 22.176 15.908 23.352 ;
     RECT  15.325 24.384 15.908 24.792 ;
     RECT  15.325 26.784 15.908 28.248 ;
     RECT  13.504 29.76 15.908 30.792 ;
     RECT  15.217 31.776 15.908 36.888 ;
     RECT  14.681 38.16 15.908 39.864 ;
     RECT  15.793 41.04 15.908 44.472 ;
     RECT  15.793 45.696 15.908 46.92 ;
     RECT  15.637 48.144 15.908 52.44 ;
     RECT  15.217 53.472 15.908 56.712 ;
     RECT  15.757 57.888 15.908 59.208 ;
     RECT  15.217 60.864 15.908 63.24 ;
     RECT  15.908 2.148 16.012 75.612 ;
     RECT  16.012 2.418 16.204 75.342 ;
     RECT  16.204 37.92 16.337 46.248 ;
     RECT  16.204 47.856 16.355 52.728 ;
     RECT  16.204 25.632 16.381 30.408 ;
     RECT  16.355 47.856 16.403 49.608 ;
     RECT  16.337 37.92 16.409 44.472 ;
     RECT  16.204 4.752 16.445 15.288 ;
     RECT  16.337 45.696 16.553 46.248 ;
     RECT  16.204 56.784 16.589 58.2 ;
     RECT  16.355 50.688 16.643 52.728 ;
     RECT  16.204 24.384 16.697 24.408 ;
     RECT  16.409 44.448 16.733 44.472 ;
     RECT  16.381 26.736 16.769 30.408 ;
     RECT  16.403 47.856 16.797 49.512 ;
     RECT  16.643 50.832 16.805 52.728 ;
     RECT  16.589 56.976 16.835 58.2 ;
     RECT  16.204 2.784 16.913 3.432 ;
     RECT  16.204 16.32 16.913 17.064 ;
     RECT  16.769 26.736 16.949 29.448 ;
     RECT  16.204 54.048 16.949 54.072 ;
     RECT  16.949 28.224 17.027 29.448 ;
     RECT  16.949 26.736 17.065 26.76 ;
     RECT  16.835 56.976 17.129 58.152 ;
     RECT  16.553 46.224 17.165 46.248 ;
     RECT  16.204 22.752 17.237 22.872 ;
     RECT  16.409 37.92 17.273 43.32 ;
     RECT  16.445 4.752 17.309 14.952 ;
     RECT  16.204 60.624 17.309 62.472 ;
     RECT  17.273 37.92 17.363 42.888 ;
     RECT  16.204 31.92 17.557 33.048 ;
     RECT  17.027 29.088 17.561 29.448 ;
     RECT  17.557 31.68 17.603 33.048 ;
     RECT  16.204 55.536 17.605 55.8 ;
     RECT  16.204 34.176 17.701 35.016 ;
     RECT  17.605 55.536 17.708 56.424 ;
     RECT  16.797 49.488 17.737 49.512 ;
     RECT  16.805 50.832 17.737 52.008 ;
     RECT  17.557 54.336 17.749 54.36 ;
     RECT  17.708 55.392 17.749 56.424 ;
     RECT  17.309 4.752 17.809 4.776 ;
     RECT  17.413 46.704 17.941 46.728 ;
     RECT  16.797 47.856 17.941 48.168 ;
     RECT  17.941 46.704 17.953 48.168 ;
     RECT  16.913 16.32 17.989 16.872 ;
     RECT  17.953 18.192 17.989 18.216 ;
     RECT  16.204 59.28 17.989 59.64 ;
     RECT  17.309 60.624 17.989 61.128 ;
     RECT  17.309 5.76 17.996 14.952 ;
     RECT  17.989 16.32 17.996 18.216 ;
     RECT  17.953 46.704 18.061 48.264 ;
     RECT  17.737 49.488 18.061 52.008 ;
     RECT  17.737 52.992 18.061 53.016 ;
     RECT  17.749 54.336 18.061 56.424 ;
     RECT  17.701 34.176 18.205 35.496 ;
     RECT  17.917 36.672 18.205 36.696 ;
     RECT  17.996 5.76 18.229 18.216 ;
     RECT  18.061 19.92 18.229 19.944 ;
     RECT  18.133 21.168 18.229 21.192 ;
     RECT  17.237 22.752 18.277 22.776 ;
     RECT  17.603 31.68 18.277 31.992 ;
     RECT  17.941 45.36 18.277 45.384 ;
     RECT  17.363 37.92 18.349 39.336 ;
     RECT  18.061 46.704 18.349 52.008 ;
     RECT  18.061 52.992 18.373 56.424 ;
     RECT  17.129 57.408 18.373 58.152 ;
     RECT  17.953 27.312 18.385 27.336 ;
     RECT  18.349 37.92 18.385 39.528 ;
     RECT  17.363 40.608 18.385 42.888 ;
     RECT  17.989 59.28 18.385 61.128 ;
     RECT  18.277 31.392 18.469 31.992 ;
     RECT  18.277 45.12 18.469 45.384 ;
     RECT  18.349 46.656 18.469 52.008 ;
     RECT  18.373 52.992 18.469 58.152 ;
     RECT  18.385 59.184 18.469 61.128 ;
     RECT  16.381 25.632 18.529 25.656 ;
     RECT  16.913 3.408 18.608 3.432 ;
     RECT  17.809 4.416 18.608 4.776 ;
     RECT  18.229 5.76 18.608 18.84 ;
     RECT  18.229 19.92 18.608 21.24 ;
     RECT  18.277 22.224 18.608 22.776 ;
     RECT  18.529 24.912 18.608 25.656 ;
     RECT  18.385 26.88 18.608 27.336 ;
     RECT  17.561 29.232 18.608 29.448 ;
     RECT  18.469 30.96 18.608 31.992 ;
     RECT  17.603 33.024 18.608 33.048 ;
     RECT  18.205 34.176 18.608 36.696 ;
     RECT  18.385 37.92 18.608 42.888 ;
     RECT  18.469 44.448 18.608 45.384 ;
     RECT  18.469 46.656 18.608 61.128 ;
     RECT  17.309 62.16 18.608 62.472 ;
     RECT  18.608 2.148 18.712 75.612 ;
     RECT  18.712 2.418 18.904 75.342 ;
     RECT  18.904 22.224 18.965 22.776 ;
     RECT  18.904 37.392 18.965 41.64 ;
     RECT  18.904 27.888 19.043 28.824 ;
     RECT  18.904 58.656 19.091 59.304 ;
     RECT  18.904 10.848 19.109 13.944 ;
     RECT  18.965 22.656 19.109 22.776 ;
     RECT  18.904 46.08 19.181 55.992 ;
     RECT  18.904 62.16 19.181 62.184 ;
     RECT  18.904 56.976 19.187 57.624 ;
     RECT  18.904 19.968 19.217 21.192 ;
     RECT  18.965 37.584 19.283 41.64 ;
     RECT  19.091 59.28 19.289 59.304 ;
     RECT  19.187 56.976 19.379 57.432 ;
     RECT  19.217 19.968 19.433 20.616 ;
     RECT  19.181 46.08 19.433 55.8 ;
     RECT  18.904 24.912 19.505 26.904 ;
     RECT  18.904 60.96 19.505 60.984 ;
     RECT  19.433 20.112 19.541 20.616 ;
     RECT  19.433 52.272 19.715 55.8 ;
     RECT  19.715 52.272 19.756 55.224 ;
     RECT  19.379 56.976 19.757 57.384 ;
     RECT  19.505 24.912 19.907 25.944 ;
     RECT  19.043 28.8 19.933 28.824 ;
     RECT  19.433 46.08 19.955 51.144 ;
     RECT  19.933 28.8 19.964 29.064 ;
     RECT  18.904 30.24 19.964 36.36 ;
     RECT  18.904 43.344 19.964 44.76 ;
     RECT  19.964 28.8 19.973 36.36 ;
     RECT  19.757 56.976 20.045 57 ;
     RECT  19.973 29.04 20.051 36.36 ;
     RECT  19.964 42.576 20.051 44.76 ;
     RECT  18.904 15.168 20.081 16.248 ;
     RECT  20.051 43.872 20.081 44.76 ;
     RECT  18.904 4.128 20.113 9.816 ;
     RECT  20.051 30.24 20.113 36.36 ;
     RECT  19.283 37.584 20.113 41.256 ;
     RECT  19.907 24.912 20.153 25.752 ;
     RECT  19.756 54.144 20.153 55.224 ;
     RECT  19.955 46.08 20.243 50.184 ;
     RECT  20.081 43.92 20.284 44.76 ;
     RECT  20.113 3.888 20.293 9.816 ;
     RECT  19.109 11.376 20.293 13.944 ;
     RECT  20.243 46.08 20.297 49.608 ;
     RECT  20.284 43.92 20.305 43.944 ;
     RECT  20.113 30.24 20.339 41.256 ;
     RECT  20.051 42.576 20.725 42.6 ;
     RECT  20.473 58.656 20.725 58.68 ;
     RECT  20.339 31.92 20.761 41.256 ;
     RECT  20.725 42.288 20.761 42.6 ;
     RECT  20.725 58.656 20.761 59.016 ;
     RECT  20.761 57.984 20.833 59.016 ;
     RECT  20.081 16.08 20.977 16.248 ;
     RECT  20.833 57.552 20.977 59.016 ;
     RECT  20.339 30.24 21.049 30.264 ;
     RECT  20.153 54.816 21.085 55.224 ;
     RECT  20.977 57.552 21.085 59.256 ;
     RECT  20.473 62.064 21.085 62.088 ;
     RECT  21.068 63.456 21.085 63.48 ;
     RECT  18.904 18.48 21.109 18.504 ;
     RECT  21.085 62.064 21.109 63.48 ;
     RECT  21.085 54.816 21.157 56.04 ;
     RECT  21.085 57.024 21.157 59.256 ;
     RECT  21.049 30.048 21.193 30.264 ;
     RECT  20.293 3.264 21.308 9.816 ;
     RECT  20.293 11.376 21.308 14.856 ;
     RECT  20.977 16.08 21.308 16.584 ;
     RECT  21.109 17.664 21.308 18.504 ;
     RECT  19.541 20.112 21.308 20.568 ;
     RECT  19.109 22.752 21.308 22.776 ;
     RECT  20.153 25.488 21.308 25.752 ;
     RECT  21.193 29.616 21.308 30.264 ;
     RECT  20.761 31.92 21.308 42.6 ;
     RECT  20.533 44.976 21.308 45 ;
     RECT  20.297 46.08 21.308 48.168 ;
     RECT  20.297 49.152 21.308 49.608 ;
     RECT  19.756 52.272 21.308 53.016 ;
     RECT  21.157 54.816 21.308 59.832 ;
     RECT  21.109 61.632 21.308 64.152 ;
     RECT  21.157 66.72 21.308 67.848 ;
     RECT  21.308 2.148 21.412 75.612 ;
     RECT  21.412 2.148 21.541 75.342 ;
     RECT  21.541 1.728 21.604 75.342 ;
     RECT  21.604 1.728 21.665 1.752 ;
     RECT  21.604 3.12 21.665 13.272 ;
     RECT  21.604 31.104 21.665 43.368 ;
     RECT  21.604 67.248 21.665 67.848 ;
     RECT  21.604 46.56 21.737 55.992 ;
     RECT  21.604 57.648 21.773 58.152 ;
     RECT  21.665 3.12 21.809 9.144 ;
     RECT  21.737 48.768 21.875 55.992 ;
     RECT  21.604 27.936 21.881 27.96 ;
     RECT  21.604 15.84 22.061 17.16 ;
     RECT  21.875 48.768 22.115 55.944 ;
     RECT  22.061 16.224 22.133 17.16 ;
     RECT  21.604 44.448 22.156 45.24 ;
     RECT  21.809 5.808 22.169 9.144 ;
     RECT  21.665 10.128 22.205 13.272 ;
     RECT  21.604 24.048 22.205 26.232 ;
     RECT  21.604 28.944 22.307 30.072 ;
     RECT  21.809 3.12 22.313 4.728 ;
     RECT  22.205 25.824 22.313 26.232 ;
     RECT  21.665 31.104 22.348 36.36 ;
     RECT  21.604 64.56 22.403 64.584 ;
     RECT  22.348 31.872 22.493 36.36 ;
     RECT  21.604 21.936 22.529 23.016 ;
     RECT  21.665 37.92 22.595 43.368 ;
     RECT  21.604 62.784 22.633 63.48 ;
     RECT  22.205 10.128 22.637 10.872 ;
     RECT  22.493 31.872 22.691 34.536 ;
     RECT  22.169 7.2 22.693 9.144 ;
     RECT  22.637 10.128 22.693 10.584 ;
     RECT  21.604 65.664 22.7 65.688 ;
     RECT  22.493 35.664 22.705 36.36 ;
     RECT  22.595 37.92 22.705 39.816 ;
     RECT  21.737 46.56 22.741 47.592 ;
     RECT  22.115 48.768 22.741 49.752 ;
     RECT  22.7 65.664 22.741 65.88 ;
     RECT  21.665 67.248 22.741 67.272 ;
     RECT  22.307 28.944 22.777 29.64 ;
     RECT  22.741 46.56 22.777 49.752 ;
     RECT  22.115 50.784 22.781 55.944 ;
     RECT  22.633 62.16 22.781 63.48 ;
     RECT  22.781 62.16 22.787 62.808 ;
     RECT  22.741 65.664 22.787 67.272 ;
     RECT  22.777 28.704 22.817 29.64 ;
     RECT  22.313 3.12 22.849 3.144 ;
     RECT  22.156 44.448 22.853 44.472 ;
     RECT  22.787 66.72 22.853 67.272 ;
     RECT  21.773 57.648 22.877 57.672 ;
     RECT  22.777 45.6 22.889 49.752 ;
     RECT  22.781 51.072 22.889 55.944 ;
     RECT  22.595 40.896 22.961 43.368 ;
     RECT  22.877 57.6 22.961 57.672 ;
     RECT  22.889 52.176 22.993 55.944 ;
     RECT  22.169 5.808 23.137 5.832 ;
     RECT  22.693 7.2 23.137 10.584 ;
     RECT  22.787 62.16 23.245 62.76 ;
     RECT  22.313 4.704 23.353 4.728 ;
     RECT  23.137 5.808 23.353 10.584 ;
     RECT  22.205 12.288 23.353 13.272 ;
     RECT  22.133 16.224 23.353 17.112 ;
     RECT  23.065 18.24 23.353 18.264 ;
     RECT  22.691 31.872 23.365 34.392 ;
     RECT  23.353 16.224 23.425 18.264 ;
     RECT  23.425 16.224 23.461 18.6 ;
     RECT  23.245 61.776 23.497 62.76 ;
     RECT  22.961 57.648 23.605 57.672 ;
     RECT  22.705 35.664 23.641 39.816 ;
     RECT  23.461 15.984 23.677 18.6 ;
     RECT  23.365 31.536 23.677 34.392 ;
     RECT  22.889 47.856 23.701 49.752 ;
     RECT  22.529 22.752 23.749 23.016 ;
     RECT  22.205 24.048 23.749 24.072 ;
     RECT  23.677 15.456 23.785 18.6 ;
     RECT  21.604 19.632 23.785 19.656 ;
     RECT  23.497 61.44 23.797 62.76 ;
     RECT  23.533 25.632 23.893 25.656 ;
     RECT  22.787 65.664 23.893 65.688 ;
     RECT  23.353 4.704 23.929 10.584 ;
     RECT  21.604 20.832 23.929 20.856 ;
     RECT  22.813 68.976 23.929 69 ;
     RECT  23.893 25.632 23.965 26.04 ;
     RECT  23.701 47.856 23.965 50.04 ;
     RECT  22.889 51.072 23.965 51.096 ;
     RECT  23.929 68.928 23.965 69 ;
     RECT  23.965 68.928 24.001 69.048 ;
     RECT  22.849 2.976 24.008 3.144 ;
     RECT  23.929 4.128 24.008 10.584 ;
     RECT  23.353 12.144 24.008 13.272 ;
     RECT  23.785 15.456 24.008 19.656 ;
     RECT  23.929 20.832 24.008 21.432 ;
     RECT  23.749 22.752 24.008 24.072 ;
     RECT  23.965 25.632 24.008 26.28 ;
     RECT  23.857 27.408 24.008 27.432 ;
     RECT  22.817 28.704 24.008 29.112 ;
     RECT  23.677 30.768 24.008 34.392 ;
     RECT  23.641 35.472 24.008 39.816 ;
     RECT  22.961 40.896 24.008 42.024 ;
     RECT  22.889 45.6 24.008 46.776 ;
     RECT  23.965 47.856 24.008 51.096 ;
     RECT  22.993 52.176 24.008 56.28 ;
     RECT  23.605 57.648 24.008 58.248 ;
     RECT  23.797 60.288 24.008 62.76 ;
     RECT  23.893 65.232 24.008 65.688 ;
     RECT  24.001 68.688 24.008 69.048 ;
     RECT  23.029 70.512 24.008 70.536 ;
     RECT  23.389 73.584 24.008 73.608 ;
     RECT  24.008 2.148 24.112 75.612 ;
     RECT  24.112 2.418 24.304 75.342 ;
     RECT  24.304 36.528 24.365 39.096 ;
     RECT  24.304 40.896 24.401 41.016 ;
     RECT  24.304 2.784 24.419 11.304 ;
     RECT  24.304 19.344 24.419 21.672 ;
     RECT  24.304 26.448 24.419 26.472 ;
     RECT  24.365 36.528 24.419 38.52 ;
     RECT  24.304 12.864 24.437 13.56 ;
     RECT  24.437 13.152 24.473 13.56 ;
     RECT  24.304 30.192 24.473 31.704 ;
     RECT  24.419 2.784 24.553 11.256 ;
     RECT  24.304 28.32 24.553 29.112 ;
     RECT  24.553 2.784 24.761 5.064 ;
     RECT  24.304 68.64 24.761 69 ;
     RECT  24.553 28.32 24.833 28.344 ;
     RECT  24.304 42 24.833 45 ;
     RECT  24.761 68.688 24.869 69 ;
     RECT  24.761 2.784 24.905 4.536 ;
     RECT  24.419 19.824 24.941 21.672 ;
     RECT  24.304 50.16 24.941 53.592 ;
     RECT  24.833 42 24.977 43.56 ;
     RECT  24.833 44.592 24.977 45 ;
     RECT  24.419 37.056 25.013 38.52 ;
     RECT  24.941 19.824 25.091 21.144 ;
     RECT  24.304 70.896 25.121 70.92 ;
     RECT  24.304 33.264 25.193 35.496 ;
     RECT  24.977 44.592 25.193 44.616 ;
     RECT  24.304 64.224 25.265 65.688 ;
     RECT  24.304 57.648 25.297 60.648 ;
     RECT  24.941 51.312 25.309 53.592 ;
     RECT  25.297 57.648 25.333 61.608 ;
     RECT  24.473 30.192 25.337 31.176 ;
     RECT  25.013 37.056 25.337 38.232 ;
     RECT  24.401 40.992 25.337 41.016 ;
     RECT  24.304 46.752 25.337 47.544 ;
     RECT  25.333 57.648 25.34 61.752 ;
     RECT  24.869 68.88 25.373 69 ;
     RECT  25.265 65.424 25.379 65.688 ;
     RECT  25.337 46.752 25.405 46.872 ;
     RECT  25.34 56.928 25.427 61.752 ;
     RECT  24.304 24.624 25.445 24.648 ;
     RECT  24.941 50.16 25.477 50.184 ;
     RECT  25.265 64.224 25.477 64.344 ;
     RECT  25.091 19.92 25.481 21.144 ;
     RECT  24.553 6.288 25.525 11.256 ;
     RECT  24.304 15.456 25.549 18.168 ;
     RECT  25.484 40.848 25.549 40.872 ;
     RECT  25.427 57.696 25.553 61.752 ;
     RECT  25.553 59.76 25.571 61.752 ;
     RECT  25.549 40.752 25.661 40.872 ;
     RECT  25.553 57.696 25.661 58.776 ;
     RECT  25.405 46.464 25.669 46.872 ;
     RECT  24.304 22.752 25.697 23.304 ;
     RECT  24.977 42 25.697 42.84 ;
     RECT  25.477 49.44 25.697 50.184 ;
     RECT  25.525 6.144 25.715 11.256 ;
     RECT  25.669 46.224 25.715 46.872 ;
     RECT  25.697 49.44 25.715 49.992 ;
     RECT  24.473 13.296 25.729 13.56 ;
     RECT  25.193 34.368 25.801 35.496 ;
     RECT  25.729 13.056 25.909 13.56 ;
     RECT  25.337 31.152 25.909 31.176 ;
     RECT  25.477 64.08 25.981 64.344 ;
     RECT  25.909 31.152 26.053 31.8 ;
     RECT  25.193 33.264 26.053 33.336 ;
     RECT  24.905 3.36 26.125 4.536 ;
     RECT  25.549 15.408 26.125 18.168 ;
     RECT  25.909 13.056 26.156 13.896 ;
     RECT  26.156 13.056 26.197 14.376 ;
     RECT  26.101 21.168 26.269 21.624 ;
     RECT  25.697 22.752 26.269 23.064 ;
     RECT  25.981 63.792 26.269 64.344 ;
     RECT  25.715 6.144 26.305 9.144 ;
     RECT  25.801 34.368 26.389 35.88 ;
     RECT  25.337 37.632 26.389 38.232 ;
     RECT  25.441 54.096 26.413 54.168 ;
     RECT  26.125 26.784 26.521 26.808 ;
     RECT  25.571 60.288 26.593 61.752 ;
     RECT  26.053 31.152 26.665 33.336 ;
     RECT  26.389 34.368 26.665 38.232 ;
     RECT  25.661 58.656 26.665 58.68 ;
     RECT  25.715 46.224 26.701 46.776 ;
     RECT  26.125 2.88 26.708 4.536 ;
     RECT  26.305 5.952 26.708 9.144 ;
     RECT  25.715 10.32 26.708 11.256 ;
     RECT  26.197 12.528 26.708 14.376 ;
     RECT  26.125 15.408 26.708 18.264 ;
     RECT  25.481 19.92 26.708 19.944 ;
     RECT  26.269 21.168 26.708 23.064 ;
     RECT  26.665 25.056 26.708 25.08 ;
     RECT  26.521 26.208 26.708 26.808 ;
     RECT  26.629 30.048 26.708 30.072 ;
     RECT  26.665 31.152 26.708 38.232 ;
     RECT  25.661 40.752 26.708 40.776 ;
     RECT  25.697 42.192 26.708 42.84 ;
     RECT  26.701 46.224 26.708 47.688 ;
     RECT  25.715 49.44 26.708 49.464 ;
     RECT  25.309 51.312 26.708 53.016 ;
     RECT  26.413 54.096 26.708 54.456 ;
     RECT  26.233 55.968 26.708 55.992 ;
     RECT  26.665 58.128 26.708 58.68 ;
     RECT  26.593 60.288 26.708 62.568 ;
     RECT  26.269 63.6 26.708 64.344 ;
     RECT  25.379 65.424 26.708 65.448 ;
     RECT  26.161 67.248 26.708 67.272 ;
     RECT  25.373 68.928 26.708 69 ;
     RECT  25.729 73.248 26.708 73.272 ;
     RECT  26.708 2.148 26.812 75.612 ;
     RECT  26.812 2.418 27.004 75.342 ;
     RECT  27.004 33.024 27.029 33.336 ;
     RECT  27.004 52.704 27.065 54.12 ;
     RECT  27.004 60.576 27.065 61.752 ;
     RECT  27.004 70.368 27.137 70.584 ;
     RECT  27.004 46.224 27.155 46.872 ;
     RECT  27.004 30.048 27.173 31.8 ;
     RECT  27.155 46.224 27.245 46.776 ;
     RECT  27.004 22.368 27.251 23.928 ;
     RECT  27.004 20.544 27.317 21.192 ;
     RECT  27.317 20.544 27.347 21.048 ;
     RECT  27.004 48.048 27.353 48.984 ;
     RECT  27.004 2.784 27.389 11.352 ;
     RECT  27.004 13.056 27.389 19.368 ;
     RECT  27.389 2.784 27.395 11.256 ;
     RECT  27.395 5.52 27.425 11.256 ;
     RECT  27.389 13.056 27.491 15.432 ;
     RECT  27.353 48.96 27.497 48.984 ;
     RECT  27.251 22.464 27.533 23.928 ;
     RECT  27.065 60.576 27.569 60.6 ;
     RECT  27.004 65.136 27.569 65.544 ;
     RECT  27.425 5.52 27.641 11.016 ;
     RECT  27.395 2.784 27.893 4.2 ;
     RECT  27.533 22.752 27.929 23.928 ;
     RECT  27.004 38.208 27.929 38.76 ;
     RECT  27.004 44.736 27.929 44.856 ;
     RECT  27.065 52.704 27.964 53.928 ;
     RECT  27.137 70.368 27.965 70.392 ;
     RECT  27.173 30.048 27.971 31.368 ;
     RECT  27.491 15.216 28.001 15.432 ;
     RECT  27.389 16.464 28.001 19.368 ;
     RECT  28.001 17.376 28.028 19.368 ;
     RECT  27.004 27.312 28.033 27.336 ;
     RECT  27.004 55.968 28.037 55.992 ;
     RECT  27.245 46.224 28.069 46.248 ;
     RECT  27.004 58.752 28.069 58.776 ;
     RECT  27.004 36.384 28.073 36.6 ;
     RECT  27.004 51.456 28.073 51.48 ;
     RECT  27.964 53.568 28.145 53.928 ;
     RECT  27.004 74.016 28.213 74.472 ;
     RECT  27.491 13.056 28.217 14.232 ;
     RECT  28.033 26.976 28.249 27.336 ;
     RECT  27.004 42.192 28.249 42.216 ;
     RECT  27.641 5.52 28.253 10.92 ;
     RECT  27.971 30.144 28.253 31.368 ;
     RECT  28.069 58.704 28.253 58.776 ;
     RECT  28.249 26.304 28.285 27.336 ;
     RECT  27.893 2.784 28.289 3.768 ;
     RECT  28.285 26.304 28.316 27.384 ;
     RECT  27.004 28.8 28.316 28.824 ;
     RECT  28.249 42.192 28.321 42.936 ;
     RECT  28.213 73.488 28.325 74.472 ;
     RECT  27.004 25.008 28.357 25.032 ;
     RECT  28.316 26.304 28.357 28.824 ;
     RECT  27.004 34.464 28.357 34.488 ;
     RECT  28.321 42.192 28.357 44.616 ;
     RECT  28.357 34.32 28.393 34.488 ;
     RECT  28.253 58.704 28.397 58.728 ;
     RECT  28.357 25.008 28.403 28.824 ;
     RECT  28.316 56.4 28.403 56.424 ;
     RECT  28.028 17.376 28.429 19.464 ;
     RECT  27.347 20.544 28.429 20.568 ;
     RECT  28.403 25.008 28.429 27.336 ;
     RECT  28.357 41.424 28.429 44.616 ;
     RECT  28.217 13.056 28.537 13.608 ;
     RECT  28.429 41.328 28.609 44.616 ;
     RECT  28.253 5.52 28.681 5.736 ;
     RECT  27.004 67.584 28.693 67.8 ;
     RECT  28.393 34.32 28.7 34.872 ;
     RECT  28.681 5.472 28.717 5.736 ;
     RECT  28.7 34.32 28.741 35.4 ;
     RECT  28.073 36.384 28.741 36.504 ;
     RECT  28.253 6.816 28.861 10.92 ;
     RECT  27.929 38.208 28.861 38.232 ;
     RECT  28.717 5.28 28.897 5.736 ;
     RECT  28.393 60.672 28.897 60.696 ;
     RECT  27.065 61.728 28.897 61.752 ;
     RECT  28.537 12.72 29.077 13.608 ;
     RECT  28.001 15.216 29.077 15.24 ;
     RECT  28.429 17.376 29.077 20.568 ;
     RECT  28.325 73.488 29.084 73.512 ;
     RECT  29.084 72.96 29.125 73.512 ;
     RECT  27.929 22.752 29.132 23.352 ;
     RECT  28.429 24.912 29.132 27.336 ;
     RECT  27.029 33.024 29.293 33.048 ;
     RECT  28.969 21.648 29.329 21.672 ;
     RECT  29.132 22.752 29.329 27.336 ;
     RECT  28.289 2.784 29.408 3.624 ;
     RECT  28.897 5.232 29.408 5.736 ;
     RECT  28.861 6.816 29.408 10.968 ;
     RECT  29.077 11.952 29.408 13.608 ;
     RECT  29.077 14.64 29.408 15.24 ;
     RECT  28.825 16.224 29.408 16.248 ;
     RECT  29.077 17.328 29.408 20.568 ;
     RECT  29.329 21.648 29.408 27.336 ;
     RECT  28.403 28.8 29.408 28.824 ;
     RECT  28.253 30.144 29.408 30.888 ;
     RECT  29.293 33.024 29.408 33.144 ;
     RECT  28.741 34.32 29.408 36.504 ;
     RECT  28.861 37.968 29.408 38.232 ;
     RECT  28.609 40.464 29.408 44.616 ;
     RECT  28.069 45.6 29.408 46.248 ;
     RECT  28.825 50.688 29.408 50.712 ;
     RECT  28.145 53.904 29.408 53.928 ;
     RECT  28.357 57.408 29.408 57.432 ;
     RECT  28.897 60.672 29.408 61.752 ;
     RECT  28.652 65.232 29.408 65.256 ;
     RECT  28.693 66.72 29.408 67.8 ;
     RECT  27.004 68.928 29.408 68.952 ;
     RECT  29.005 70.128 29.408 70.152 ;
     RECT  29.125 72.432 29.408 73.512 ;
     RECT  29.408 2.148 29.512 75.612 ;
     RECT  29.512 2.256 29.704 75.342 ;
     RECT  29.704 5.28 29.729 8.472 ;
     RECT  29.729 5.52 29.765 8.472 ;
     RECT  29.704 61.728 29.801 62.76 ;
     RECT  29.704 72.432 29.801 72.456 ;
     RECT  29.765 5.52 29.843 7.176 ;
     RECT  29.765 8.16 29.843 8.472 ;
     RECT  29.843 8.448 29.873 8.472 ;
     RECT  29.704 30.144 30.017 33.24 ;
     RECT  29.704 15.024 30.125 16.104 ;
     RECT  29.704 41.232 30.233 41.256 ;
     RECT  30.125 15.264 30.269 15.672 ;
     RECT  30.017 31.968 30.269 33.24 ;
     RECT  29.704 58.704 30.305 58.728 ;
     RECT  30.269 31.968 30.341 32.52 ;
     RECT  29.704 56.736 30.341 56.856 ;
     RECT  29.843 5.52 30.377 6.6 ;
     RECT  29.704 12.24 30.377 12.552 ;
     RECT  29.704 44.496 30.419 44.52 ;
     RECT  29.704 18.24 30.449 20.04 ;
     RECT  29.704 26.64 30.449 28.44 ;
     RECT  30.449 18.816 30.515 20.04 ;
     RECT  29.704 22.032 30.515 22.056 ;
     RECT  29.704 2.256 30.521 2.28 ;
     RECT  30.515 19.152 30.557 20.04 ;
     RECT  29.801 61.872 30.557 62.76 ;
     RECT  29.704 45.792 30.593 45.816 ;
     RECT  29.704 49.584 30.593 50.76 ;
     RECT  29.704 23.952 30.629 25.56 ;
     RECT  29.704 66.768 30.629 66.792 ;
     RECT  30.593 49.584 30.665 49.848 ;
     RECT  29.704 64.944 30.665 64.968 ;
     RECT  29.704 9.552 30.697 10.968 ;
     RECT  29.704 3.888 30.737 3.912 ;
     RECT  30.557 19.152 30.755 19.368 ;
     RECT  30.665 49.584 30.773 49.704 ;
     RECT  29.704 53.328 30.773 53.928 ;
     RECT  30.341 56.736 30.773 56.76 ;
     RECT  30.377 12.528 30.805 12.552 ;
     RECT  30.449 28.176 30.805 28.44 ;
     RECT  30.377 6 30.809 6.6 ;
     RECT  30.773 49.68 30.809 49.704 ;
     RECT  29.704 43.104 30.841 43.128 ;
     RECT  30.805 28.176 30.917 29.064 ;
     RECT  30.809 6.576 30.985 6.6 ;
     RECT  30.709 20.592 31.021 20.616 ;
     RECT  30.629 25.056 31.021 25.56 ;
     RECT  30.805 12.528 31.103 12.648 ;
     RECT  29.704 34.368 31.129 34.392 ;
     RECT  29.704 38.208 31.237 38.232 ;
     RECT  31.103 12.528 31.285 13.608 ;
     RECT  31.129 73.776 31.285 73.8 ;
     RECT  31.129 34.368 31.309 35.352 ;
     RECT  31.237 37.44 31.309 38.232 ;
     RECT  31.237 39.552 31.309 39.576 ;
     RECT  30.985 6.576 31.333 7.272 ;
     RECT  31.273 8.496 31.333 8.52 ;
     RECT  30.697 9.552 31.333 11.496 ;
     RECT  30.017 30.144 31.477 30.6 ;
     RECT  31.453 22.848 31.489 22.872 ;
     RECT  30.841 42.768 31.561 43.128 ;
     RECT  31.201 40.8 31.669 40.824 ;
     RECT  31.561 41.856 31.669 43.128 ;
     RECT  30.755 19.248 31.777 19.272 ;
     RECT  31.021 25.056 31.861 25.608 ;
     RECT  30.449 26.64 31.861 27.096 ;
     RECT  30.917 28.176 31.861 28.44 ;
     RECT  31.333 6.576 31.885 11.496 ;
     RECT  31.285 12.528 31.885 13.992 ;
     RECT  31.129 17.04 31.885 17.064 ;
     RECT  31.489 22.848 31.885 23.64 ;
     RECT  30.773 53.904 31.885 53.928 ;
     RECT  30.341 31.968 31.909 31.992 ;
     RECT  29.704 60.672 31.909 60.696 ;
     RECT  30.557 61.872 31.909 61.896 ;
     RECT  31.909 31.968 31.921 32.52 ;
     RECT  31.309 33.6 31.921 35.352 ;
     RECT  31.909 60.144 31.957 61.896 ;
     RECT  31.057 2.832 31.993 2.856 ;
     RECT  29.704 47.568 31.993 47.592 ;
     RECT  31.957 51.936 31.993 51.96 ;
     RECT  31.957 66.576 31.993 66.6 ;
     RECT  31.993 2.832 32.108 3.096 ;
     RECT  31.533 5.472 32.108 5.496 ;
     RECT  31.885 6.576 32.108 13.992 ;
     RECT  30.269 15.36 32.108 15.672 ;
     RECT  31.885 16.656 32.108 17.064 ;
     RECT  31.777 18.144 32.108 18.168 ;
     RECT  31.777 19.248 32.108 19.368 ;
     RECT  31.021 20.592 32.108 21.144 ;
     RECT  31.885 22.848 32.108 23.688 ;
     RECT  31.861 25.056 32.108 25.656 ;
     RECT  31.861 26.64 32.108 28.44 ;
     RECT  31.477 29.616 32.108 30.6 ;
     RECT  31.921 31.968 32.108 35.352 ;
     RECT  31.309 37.44 32.108 39.576 ;
     RECT  31.669 40.8 32.108 43.128 ;
     RECT  31.057 44.928 32.108 44.952 ;
     RECT  31.993 47.568 32.108 47.88 ;
     RECT  31.993 51.648 32.108 51.96 ;
     RECT  31.885 53.328 32.108 53.928 ;
     RECT  31.957 55.536 32.108 55.56 ;
     RECT  31.777 56.88 32.108 56.904 ;
     RECT  31.957 58.128 32.108 58.152 ;
     RECT  31.957 60.144 32.108 62.76 ;
     RECT  31.909 64.416 32.108 64.44 ;
     RECT  31.021 65.472 32.108 65.496 ;
     RECT  31.993 66.576 32.108 67.416 ;
     RECT  31.245 69.408 32.108 69.432 ;
     RECT  31.741 70.704 32.108 70.728 ;
     RECT  32.029 72.48 32.108 72.504 ;
     RECT  31.285 73.776 32.108 74.328 ;
     RECT  32.108 2.148 32.212 75.612 ;
     RECT  32.212 2.418 32.404 75.342 ;
     RECT  32.404 34.896 32.501 34.92 ;
     RECT  32.404 7.92 32.537 7.944 ;
     RECT  32.404 67.392 32.537 68.376 ;
     RECT  32.404 62.736 32.573 62.76 ;
     RECT  32.404 55.824 32.579 56.904 ;
     RECT  32.404 9.792 32.601 13.176 ;
     RECT  32.601 9.792 32.609 10.296 ;
     RECT  32.404 60.384 32.681 61.08 ;
     RECT  32.404 72.48 32.681 72.744 ;
     RECT  32.404 53.808 32.723 54.648 ;
     RECT  32.404 38.208 32.753 38.76 ;
     RECT  32.404 49.824 32.753 50.76 ;
     RECT  32.404 20.592 32.825 24.504 ;
     RECT  32.404 30.576 32.825 30.84 ;
     RECT  32.404 42.768 32.825 43.128 ;
     RECT  32.404 15.216 32.867 18.168 ;
     RECT  32.404 41.376 32.897 41.4 ;
     RECT  32.404 44.928 32.897 45.192 ;
     RECT  32.404 46.752 32.897 48.456 ;
     RECT  32.867 17.136 32.908 17.88 ;
     RECT  32.825 21.552 32.915 24.504 ;
     RECT  32.404 19.344 32.933 19.368 ;
     RECT  32.897 45.168 33.011 45.192 ;
     RECT  32.867 15.216 33.041 16.008 ;
     RECT  32.404 32.832 33.041 33.768 ;
     RECT  32.681 60.384 33.041 60.984 ;
     RECT  32.601 11.424 33.077 13.176 ;
     RECT  32.897 46.752 33.077 47.304 ;
     RECT  32.404 3.072 33.107 3.096 ;
     RECT  32.404 4.512 33.107 6.84 ;
     RECT  32.825 30.576 33.113 30.792 ;
     RECT  32.753 49.968 33.113 50.76 ;
     RECT  33.107 4.512 33.149 4.776 ;
     RECT  32.723 53.808 33.149 53.928 ;
     RECT  32.404 58.56 33.149 58.584 ;
     RECT  33.041 33.072 33.257 33.768 ;
     RECT  32.404 26.784 33.329 28.488 ;
     RECT  32.537 67.584 33.329 68.376 ;
     RECT  32.404 51.936 33.433 51.96 ;
     RECT  33.077 11.424 33.437 13.032 ;
     RECT  32.908 17.136 33.473 17.16 ;
     RECT  33.113 49.968 33.473 49.992 ;
     RECT  33.149 4.512 33.545 4.536 ;
     RECT  33.107 6.288 33.545 6.84 ;
     RECT  32.681 72.48 33.545 72.504 ;
     RECT  32.915 22.8 33.689 24.504 ;
     RECT  33.545 6.816 33.757 6.84 ;
     RECT  33.257 33.072 33.761 33.24 ;
     RECT  33.077 47.28 33.761 47.304 ;
     RECT  33.433 51.84 33.793 51.96 ;
     RECT  32.609 10.032 33.829 10.296 ;
     RECT  33.757 6.816 33.833 7.416 ;
     RECT  33.041 60.384 33.865 60.84 ;
     RECT  32.753 38.208 33.901 38.568 ;
     RECT  33.149 53.904 33.937 53.928 ;
     RECT  33.829 9.648 33.973 10.296 ;
     RECT  33.437 11.424 33.973 11.496 ;
     RECT  33.901 37.248 34.009 38.568 ;
     RECT  33.793 51.84 34.009 52.728 ;
     RECT  32.404 69.552 34.009 69.576 ;
     RECT  34.009 69.552 34.045 69.72 ;
     RECT  34.045 69.504 34.081 69.72 ;
     RECT  33.689 23.664 34.117 24.504 ;
     RECT  34.009 37.056 34.117 38.568 ;
     RECT  34.153 41.952 34.189 41.976 ;
     RECT  33.865 59.472 34.22 60.84 ;
     RECT  32.915 21.552 34.225 21.576 ;
     RECT  32.579 56.496 34.225 56.904 ;
     RECT  32.404 66 34.225 66.024 ;
     RECT  33.577 67.056 34.225 67.08 ;
     RECT  34.225 55.872 34.261 56.904 ;
     RECT  33.113 30.768 34.268 30.792 ;
     RECT  33.761 33.12 34.297 33.24 ;
     RECT  34.189 41.376 34.309 41.976 ;
     RECT  34.297 33.12 34.333 33.336 ;
     RECT  34.117 36.24 34.333 38.568 ;
     RECT  34.225 39.84 34.333 39.864 ;
     RECT  33.329 26.832 34.357 28.488 ;
     RECT  34.268 29.904 34.357 30.792 ;
     RECT  34.333 36.24 34.369 39.864 ;
     RECT  33.577 62.736 34.477 62.76 ;
     RECT  34.477 62.736 34.501 63.528 ;
     RECT  34.333 33.12 34.513 33.576 ;
     RECT  34.369 36.096 34.585 39.864 ;
     RECT  34.309 41.04 34.585 41.976 ;
     RECT  34.585 35.856 34.597 39.864 ;
     RECT  34.297 44.352 34.597 44.376 ;
     RECT  34.117 23.664 34.621 25.224 ;
     RECT  34.585 41.04 34.765 42.312 ;
     RECT  33.329 68.352 34.765 68.376 ;
     RECT  34.513 33.12 34.768 34.104 ;
     RECT  34.597 44.352 34.801 44.472 ;
     RECT  34.369 45.984 34.801 46.008 ;
     RECT  33.833 7.392 34.808 7.416 ;
     RECT  33.973 9.648 34.808 11.496 ;
     RECT  33.437 13.008 34.808 13.032 ;
     RECT  33.829 14.64 34.808 14.664 ;
     RECT  33.041 15.936 34.808 16.008 ;
     RECT  34.165 17.424 34.808 17.448 ;
     RECT  34.225 21.264 34.808 21.576 ;
     RECT  34.621 23.664 34.808 25.32 ;
     RECT  34.357 26.832 34.808 30.792 ;
     RECT  34.768 33.024 34.808 34.104 ;
     RECT  34.597 35.28 34.808 39.864 ;
     RECT  34.765 41.04 34.808 42.504 ;
     RECT  34.801 44.352 34.808 46.008 ;
     RECT  34.729 48.96 34.808 48.984 ;
     RECT  34.009 51.312 34.808 52.728 ;
     RECT  33.937 53.904 34.808 54.216 ;
     RECT  34.261 55.872 34.808 57.384 ;
     RECT  34.22 59.04 34.808 60.84 ;
     RECT  34.501 61.872 34.808 63.528 ;
     RECT  33.613 64.896 34.808 64.92 ;
     RECT  34.225 66 34.808 67.08 ;
     RECT  34.765 68.352 34.808 68.472 ;
     RECT  34.081 69.504 34.808 69.864 ;
     RECT  34.808 2.148 34.912 75.612 ;
     RECT  34.912 2.418 35.104 75.342 ;
     RECT  35.104 62.736 35.165 63.528 ;
     RECT  35.104 22.848 35.219 24.504 ;
     RECT  35.104 60.624 35.219 60.648 ;
     RECT  35.104 70.704 35.219 70.728 ;
     RECT  35.104 50.688 35.237 53.592 ;
     RECT  35.165 63.504 35.267 63.528 ;
     RECT  35.104 68.448 35.267 68.472 ;
     RECT  35.104 32.016 35.273 42.6 ;
     RECT  35.104 25.584 35.28 30.936 ;
     RECT  35.273 32.016 35.308 34.488 ;
     RECT  35.104 11.472 35.345 11.496 ;
     RECT  35.104 44.352 35.345 49.608 ;
     RECT  35.104 54.672 35.363 55.416 ;
     RECT  35.363 55.392 35.404 55.416 ;
     RECT  35.219 22.848 35.417 24.12 ;
     RECT  35.28 26.976 35.453 30.936 ;
     RECT  35.308 32.016 35.525 32.472 ;
     RECT  35.453 29.856 35.548 30.936 ;
     RECT  35.104 58.128 35.561 58.152 ;
     RECT  35.345 44.352 35.669 45.624 ;
     RECT  35.669 44.352 35.849 45.432 ;
     RECT  35.28 25.584 35.939 25.608 ;
     RECT  35.237 53.328 35.957 53.592 ;
     RECT  35.345 46.752 35.987 49.608 ;
     RECT  35.548 30.192 35.993 30.936 ;
     RECT  35.993 30.288 36.029 30.936 ;
     RECT  35.237 50.688 36.085 51.96 ;
     RECT  35.417 24.096 36.101 24.12 ;
     RECT  35.273 35.952 36.173 42.6 ;
     RECT  35.987 46.752 36.173 49.272 ;
     RECT  36.085 50.592 36.173 51.96 ;
     RECT  35.525 32.016 36.179 32.04 ;
     RECT  35.417 22.848 36.209 22.872 ;
     RECT  36.173 46.752 36.421 48.984 ;
     RECT  35.453 26.976 36.425 28.248 ;
     RECT  35.308 33.552 36.425 34.488 ;
     RECT  36.173 36 36.461 42.6 ;
     RECT  36.421 46.704 36.467 48.984 ;
     RECT  35.957 53.328 36.467 53.352 ;
     RECT  36.461 41.04 36.493 42.6 ;
     RECT  36.461 36 36.497 39.576 ;
     RECT  36.467 48.192 36.508 48.984 ;
     RECT  36.029 30.336 36.533 30.936 ;
     RECT  36.425 33.552 36.565 34.2 ;
     RECT  35.849 44.592 36.845 45.432 ;
     RECT  36.533 30.336 37.045 30.456 ;
     RECT  36.493 41.04 37.045 43.368 ;
     RECT  36.845 44.592 37.045 45.528 ;
     RECT  36.524 25.728 37.508 26.472 ;
     RECT  36.425 27.6 37.508 28.248 ;
     RECT  37.045 30.24 37.508 30.456 ;
     RECT  37.333 31.776 37.508 31.8 ;
     RECT  36.565 33.36 37.508 34.2 ;
     RECT  36.497 36 37.508 39.384 ;
     RECT  37.045 41.04 37.508 45.528 ;
     RECT  36.467 46.704 37.508 47.112 ;
     RECT  36.508 48.96 37.508 48.984 ;
     RECT  36.173 51.408 37.508 51.96 ;
     RECT  37.508 2.148 37.612 75.612 ;
     RECT  37.612 2.418 37.804 75.342 ;
     RECT  37.804 27.216 38.284 28.296 ;
     RECT  37.804 40.992 38.339 42.264 ;
     RECT  38.284 27.936 38.369 28.296 ;
     RECT  38.369 28.224 38.513 28.296 ;
     RECT  37.804 47.856 38.579 47.928 ;
     RECT  37.804 25.344 38.627 26.136 ;
     RECT  37.804 43.92 38.629 43.944 ;
     RECT  37.804 38.16 38.657 38.712 ;
     RECT  37.804 48.912 38.657 49.8 ;
     RECT  38.579 47.856 38.693 47.88 ;
     RECT  38.657 49.008 38.716 49.8 ;
     RECT  38.716 49.008 38.729 49.656 ;
     RECT  37.804 50.784 38.765 51.288 ;
     RECT  38.729 49.44 38.771 49.464 ;
     RECT  37.804 39.888 38.809 39.912 ;
     RECT  38.339 41.616 38.819 42.264 ;
     RECT  38.765 51.264 38.837 51.288 ;
     RECT  37.804 34.512 38.867 36.552 ;
     RECT  38.867 34.512 38.873 34.536 ;
     RECT  38.513 28.272 38.909 28.296 ;
     RECT  38.867 36.048 38.909 36.552 ;
     RECT  38.627 25.872 38.945 26.136 ;
     RECT  38.945 25.872 38.981 26.04 ;
     RECT  38.909 36.048 39.017 36.456 ;
     RECT  38.819 41.616 39.089 41.928 ;
     RECT  38.981 25.872 40.208 25.896 ;
     RECT  38.941 34.128 40.208 34.152 ;
     RECT  39.017 36.048 40.208 36.072 ;
     RECT  38.657 38.208 40.208 38.712 ;
     RECT  39.089 41.616 40.208 41.784 ;
     RECT  40.208 2.148 40.312 75.612 ;
     RECT  40.312 2.418 40.504 75.342 ;
     RECT  40.504 38.208 43.081 38.232 ;
     RECT  43.081 38.208 43.121 38.376 ;
     RECT  43.121 38.352 43.164 38.376 ;
     RECT  42.145 39.36 43.164 39.384 ;
    LAYER M5 ;
     RECT  6.432 0.016 12.696 0.181 ;
     RECT  6.432 0.181 12.744 1.141 ;
     RECT  6.432 1.141 12.792 2.137 ;
     RECT  21.552 0.016 21.576 2.137 ;
     RECT  2.4 2.137 2.52 2.151 ;
     RECT  5.1 2.137 5.22 2.151 ;
     RECT  6.432 2.137 13.32 2.151 ;
     RECT  15.9 2.137 16.02 2.151 ;
     RECT  18.6 2.137 18.72 2.151 ;
     RECT  21.3 2.137 21.576 2.151 ;
     RECT  24 2.137 24.12 2.151 ;
     RECT  26.7 2.137 26.82 2.151 ;
     RECT  29.4 2.137 29.52 2.151 ;
     RECT  32.1 2.137 32.22 2.151 ;
     RECT  34.8 2.137 34.92 2.151 ;
     RECT  37.5 2.137 37.62 2.151 ;
     RECT  40.2 2.137 40.32 2.151 ;
     RECT  6.432 2.151 13.512 2.339 ;
     RECT  24 2.151 24.312 2.773 ;
     RECT  26.7 2.151 27.012 2.773 ;
     RECT  32.1 2.151 32.412 2.821 ;
     RECT  6.816 2.339 13.512 2.867 ;
     RECT  6.912 2.867 13.512 2.915 ;
     RECT  26.7 2.773 27.912 2.915 ;
     RECT  31.584 2.821 32.412 3.061 ;
     RECT  24 2.773 24.792 3.155 ;
     RECT  4.032 2.821 4.056 3.253 ;
     RECT  5.1 2.151 5.412 3.253 ;
     RECT  4.032 3.253 5.412 3.299 ;
     RECT  7.008 2.915 13.512 3.397 ;
     RECT  26.7 2.915 27.012 3.925 ;
     RECT  24 3.155 24.312 4.405 ;
     RECT  7.008 3.397 13.656 4.595 ;
     RECT  4.992 3.299 5.412 4.787 ;
     RECT  21.3 2.151 21.612 4.837 ;
     RECT  14.88 2.629 14.904 4.979 ;
     RECT  31.584 3.061 33.096 5.507 ;
     RECT  18.6 2.151 18.912 5.653 ;
     RECT  24 4.405 24.408 5.653 ;
     RECT  15.9 2.151 16.212 5.701 ;
     RECT  20.928 4.837 21.612 5.747 ;
     RECT  15.9 5.701 17.016 5.891 ;
     RECT  18.6 5.653 19.608 6.133 ;
     RECT  26.7 3.925 27.384 6.323 ;
     RECT  31.872 5.507 33.096 6.323 ;
     RECT  2.4 2.151 2.712 6.805 ;
     RECT  29.4 2.151 29.712 7.141 ;
     RECT  31.872 6.323 32.412 7.237 ;
     RECT  5.1 4.787 5.412 7.381 ;
     RECT  34.8 2.151 35.112 7.381 ;
     RECT  7.344 4.595 13.656 7.523 ;
     RECT  2.4 6.805 2.856 7.619 ;
     RECT  18.6 6.133 20.184 7.619 ;
     RECT  4.992 7.381 5.412 7.957 ;
     RECT  25.536 6.133 25.56 7.957 ;
     RECT  7.344 7.523 13.512 8.003 ;
     RECT  25.536 7.957 25.704 8.147 ;
     RECT  29.4 7.141 29.832 8.195 ;
     RECT  7.632 8.003 13.512 8.579 ;
     RECT  31.344 7.237 32.412 9.155 ;
     RECT  7.632 8.579 8.112 9.539 ;
     RECT  15.9 5.891 16.212 9.637 ;
     RECT  10.5 8.579 11.736 9.779 ;
     RECT  25.68 8.147 25.704 9.779 ;
     RECT  14.832 7.765 14.856 9.971 ;
     RECT  4.944 7.957 5.412 10.067 ;
     RECT  26.7 6.323 27.012 10.165 ;
     RECT  28.176 7.381 28.2 10.165 ;
     RECT  32.1 9.155 32.412 10.261 ;
     RECT  26.7 10.165 28.2 10.309 ;
     RECT  29.4 8.195 29.712 10.309 ;
     RECT  32.1 10.261 32.568 10.309 ;
     RECT  24 5.653 24.504 10.355 ;
     RECT  26.7 10.309 29.712 10.355 ;
     RECT  6.48 9.589 6.504 10.403 ;
     RECT  22.704 9.781 22.728 10.595 ;
     RECT  15.9 9.637 16.584 10.643 ;
     RECT  4.992 10.067 5.412 10.693 ;
     RECT  18.6 7.619 19.032 10.883 ;
     RECT  4.992 10.693 5.544 10.931 ;
     RECT  26.7 10.355 27.816 10.931 ;
     RECT  31.968 10.309 32.568 10.931 ;
     RECT  10.5 9.779 11.448 11.171 ;
     RECT  17.52 10.741 17.544 11.459 ;
     RECT  31.968 10.931 32.412 11.459 ;
     RECT  20.16 7.619 20.184 11.461 ;
     RECT  15.9 10.643 16.212 11.605 ;
     RECT  15.9 11.605 16.536 11.891 ;
     RECT  18.6 10.883 18.912 11.941 ;
     RECT  29.136 10.355 29.712 11.941 ;
     RECT  15.9 11.891 16.212 12.517 ;
     RECT  26.7 10.931 27.012 12.517 ;
     RECT  32.1 11.459 32.412 12.517 ;
     RECT  9.12 8.579 9.144 12.755 ;
     RECT  24 10.355 24.408 12.899 ;
     RECT  7.8 9.539 8.112 12.901 ;
     RECT  20.16 11.461 20.328 13.045 ;
     RECT  21.3 5.747 21.612 13.045 ;
     RECT  26.208 12.517 27.012 13.045 ;
     RECT  29.088 11.941 29.712 13.139 ;
     RECT  13.104 8.579 13.512 13.573 ;
     RECT  31.152 12.517 32.412 13.619 ;
     RECT  17.712 11.941 18.912 13.859 ;
     RECT  5.1 10.931 5.544 13.909 ;
     RECT  7.344 12.901 8.112 14.243 ;
     RECT  12.528 13.573 13.512 14.291 ;
     RECT  3.888 11.941 3.912 14.387 ;
     RECT  29.136 13.139 29.712 14.629 ;
     RECT  33.84 7.381 35.112 14.675 ;
     RECT  25.92 13.045 27.012 14.773 ;
     RECT  18.144 13.859 18.912 15.349 ;
     RECT  31.296 13.619 32.412 15.395 ;
     RECT  3.936 14.773 3.96 15.491 ;
     RECT  10.5 11.171 10.812 15.589 ;
     RECT  5.1 13.909 5.592 15.829 ;
     RECT  4.848 15.829 5.592 15.875 ;
     RECT  34.8 14.675 35.112 15.925 ;
     RECT  24 12.899 24.312 15.973 ;
     RECT  15.6 12.517 16.212 16.019 ;
     RECT  32.1 15.395 32.412 16.165 ;
     RECT  2.4 7.619 2.712 16.405 ;
     RECT  25.92 14.773 27.48 16.595 ;
     RECT  10.272 15.589 10.812 16.691 ;
     RECT  2.4 16.405 3.672 16.835 ;
     RECT  18.048 15.349 18.912 17.171 ;
     RECT  13.104 14.291 13.512 17.173 ;
     RECT  29.088 14.629 29.712 17.363 ;
     RECT  34.176 15.925 35.112 17.459 ;
     RECT  14.592 15.061 14.616 17.603 ;
     RECT  13.104 17.173 13.608 17.651 ;
     RECT  23.472 15.973 24.312 17.699 ;
     RECT  13.104 17.651 13.512 17.939 ;
     RECT  26.7 16.595 27.48 18.131 ;
     RECT  7.68 14.243 8.112 18.179 ;
     RECT  32.1 16.165 32.856 18.179 ;
     RECT  2.4 16.835 2.712 18.181 ;
     RECT  10.5 16.691 10.812 18.181 ;
     RECT  9.312 17.605 9.336 18.563 ;
     RECT  4.848 15.875 5.544 18.757 ;
     RECT  10.5 18.181 11.448 18.757 ;
     RECT  29.136 17.363 29.712 18.805 ;
     RECT  18.24 17.171 18.912 18.851 ;
     RECT  29.136 18.805 30.504 18.851 ;
     RECT  29.28 18.851 30.504 19.141 ;
     RECT  24 17.699 24.312 19.333 ;
     RECT  26.7 18.131 27.012 19.333 ;
     RECT  28.08 18.757 28.104 19.333 ;
     RECT  2.304 18.181 2.712 19.379 ;
     RECT  10.032 18.757 12.168 19.427 ;
     RECT  26.7 19.333 28.104 19.475 ;
     RECT  24 19.333 24.408 19.813 ;
     RECT  4.848 18.757 6.264 19.907 ;
     RECT  18.6 18.851 18.912 19.909 ;
     RECT  26.7 19.475 27.24 19.909 ;
     RECT  29.28 19.141 30.744 19.909 ;
     RECT  28.464 19.909 30.744 20.051 ;
     RECT  20.16 13.045 21.612 20.147 ;
     RECT  10.5 19.427 11.448 20.485 ;
     RECT  20.16 20.147 20.184 20.579 ;
     RECT  28.464 20.051 29.712 20.579 ;
     RECT  30.72 20.051 30.744 20.627 ;
     RECT  26.112 19.909 27.24 21.013 ;
     RECT  24 19.813 25.08 21.155 ;
     RECT  18.24 19.909 18.912 21.251 ;
     RECT  7.8 18.179 8.112 21.301 ;
     RECT  4.848 19.907 6.168 21.493 ;
     RECT  2.4 19.379 2.712 21.541 ;
     RECT  32.1 18.179 32.412 21.541 ;
     RECT  26.112 21.013 27.336 21.635 ;
     RECT  4.848 21.493 6.552 21.971 ;
     RECT  29.4 20.579 29.712 22.021 ;
     RECT  21.3 20.147 21.612 22.741 ;
     RECT  2.4 21.541 3.336 22.835 ;
     RECT  21.12 22.741 21.612 22.981 ;
     RECT  10.5 20.485 11.832 23.123 ;
     RECT  4.848 21.971 5.544 23.173 ;
     RECT  6.528 21.971 6.552 23.173 ;
     RECT  26.7 21.635 27.336 23.269 ;
     RECT  28.368 22.885 28.392 23.269 ;
     RECT  26.7 23.269 28.392 23.317 ;
     RECT  29.4 22.021 30.504 23.317 ;
     RECT  32.1 21.541 32.904 23.411 ;
     RECT  26.7 23.317 30.504 23.939 ;
     RECT  28.368 23.939 30.504 23.987 ;
     RECT  4.848 23.173 6.552 24.179 ;
     RECT  4.896 24.179 6.552 24.371 ;
     RECT  11.808 23.123 11.832 24.469 ;
     RECT  34.8 17.459 35.112 24.469 ;
     RECT  18.6 21.251 18.912 24.901 ;
     RECT  32.1 23.411 32.412 25.045 ;
     RECT  7.8 21.301 8.232 25.093 ;
     RECT  2.4 22.835 2.712 25.285 ;
     RECT  37.5 2.151 37.812 25.333 ;
     RECT  11.808 24.469 11.88 25.523 ;
     RECT  4.944 24.371 6.552 25.573 ;
     RECT  7.8 25.093 8.28 25.573 ;
     RECT  34.8 24.469 35.208 25.573 ;
     RECT  31.392 25.045 32.412 25.619 ;
     RECT  4.944 25.573 8.28 25.621 ;
     RECT  24 21.155 24.312 25.621 ;
     RECT  21.12 22.981 22.152 25.763 ;
     RECT  21.12 25.763 21.72 25.859 ;
     RECT  18.6 24.901 19.896 25.955 ;
     RECT  15.9 16.019 16.212 26.149 ;
     RECT  23.904 25.621 24.312 26.437 ;
     RECT  34.8 25.573 35.928 26.437 ;
     RECT  37.5 25.333 38.616 26.437 ;
     RECT  13.2 17.939 13.512 26.533 ;
     RECT  31.872 25.619 32.412 26.629 ;
     RECT  4.944 25.621 8.856 26.725 ;
     RECT  15.9 26.149 16.344 26.725 ;
     RECT  14.832 24.757 14.856 26.819 ;
     RECT  18.6 25.955 19.032 26.915 ;
     RECT  10.5 23.123 10.812 27.061 ;
     RECT  18.6 26.915 18.912 27.205 ;
     RECT  4.848 26.725 8.856 27.301 ;
     RECT  10.368 27.061 10.812 27.301 ;
     RECT  28.368 23.987 29.712 27.347 ;
     RECT  23.904 26.437 24.408 27.443 ;
     RECT  2.4 25.285 3.096 27.589 ;
     RECT  4.848 27.301 10.812 27.829 ;
     RECT  18.432 27.205 18.912 27.877 ;
     RECT  2.304 27.589 3.096 27.971 ;
     RECT  24 27.443 24.408 28.309 ;
     RECT  31.296 26.629 32.412 28.451 ;
     RECT  26.7 23.939 27.012 28.789 ;
     RECT  28.368 27.347 28.392 28.789 ;
     RECT  18.432 27.877 19.032 28.835 ;
     RECT  21.12 25.859 21.612 28.933 ;
     RECT  24 28.309 24.504 29.123 ;
     RECT  11.856 25.523 11.88 29.317 ;
     RECT  13.104 26.533 13.512 29.317 ;
     RECT  34.8 26.437 38.616 29.365 ;
     RECT  15.9 26.725 17.016 29.459 ;
     RECT  32.1 28.451 32.412 29.605 ;
     RECT  4.224 27.829 10.812 29.845 ;
     RECT  11.856 29.317 13.512 29.845 ;
     RECT  34.368 29.365 38.616 29.893 ;
     RECT  20.016 29.029 20.04 30.229 ;
     RECT  20.016 30.229 20.136 30.373 ;
     RECT  21.12 28.933 22.488 30.373 ;
     RECT  2.304 27.971 2.712 30.469 ;
     RECT  31.488 29.605 32.412 30.565 ;
     RECT  30.72 30.565 32.412 30.611 ;
     RECT  4.224 29.845 13.512 30.757 ;
     RECT  18.432 28.835 18.912 30.757 ;
     RECT  24 29.123 24.408 30.757 ;
     RECT  2.304 30.469 3.048 30.805 ;
     RECT  26.7 28.789 28.392 30.851 ;
     RECT  2.304 30.805 3.144 31.379 ;
     RECT  18.432 30.757 19.032 31.427 ;
     RECT  20.016 30.373 22.488 31.525 ;
     RECT  23.712 30.757 24.408 31.525 ;
     RECT  20.016 31.525 24.408 31.619 ;
     RECT  18.432 31.427 18.912 31.669 ;
     RECT  15.9 29.459 16.584 31.909 ;
     RECT  17.568 31.669 18.912 31.909 ;
     RECT  20.112 31.619 24.408 32.003 ;
     RECT  30.72 30.611 30.744 32.003 ;
     RECT  26.7 30.851 27.012 32.293 ;
     RECT  32.1 30.611 32.412 32.485 ;
     RECT  15.9 31.909 18.912 33.011 ;
     RECT  2.4 31.379 3.144 33.013 ;
     RECT  4.224 30.757 14.424 33.013 ;
     RECT  26.064 32.293 27.012 33.299 ;
     RECT  31.92 32.485 32.412 33.731 ;
     RECT  18.432 33.011 18.912 33.973 ;
     RECT  20.304 32.003 24.408 33.973 ;
     RECT  26.7 33.299 27.012 34.405 ;
     RECT  28.368 30.851 28.392 34.499 ;
     RECT  15.9 33.011 17.352 34.741 ;
     RECT  18.432 33.973 24.408 34.741 ;
     RECT  29.4 27.347 29.712 34.741 ;
     RECT  15.9 34.741 24.408 34.883 ;
     RECT  0.24 34.933 0.264 35.173 ;
     RECT  0.192 35.173 0.264 35.269 ;
     RECT  2.4 33.013 14.424 35.317 ;
     RECT  26.016 34.405 27.012 35.363 ;
     RECT  34.32 29.893 38.616 35.461 ;
     RECT  15.9 34.883 18.912 35.507 ;
     RECT  34.32 35.461 38.856 36.467 ;
     RECT  0.144 35.269 0.264 36.515 ;
     RECT  2.4 35.317 14.856 36.515 ;
     RECT  28.752 34.741 29.712 36.515 ;
     RECT  20.208 34.883 24.408 36.563 ;
     RECT  34.32 36.467 38.808 36.563 ;
     RECT  0.192 36.515 0.264 36.613 ;
     RECT  2.4 36.515 14.568 36.613 ;
     RECT  15.9 35.507 17.352 36.661 ;
     RECT  18.432 35.507 18.912 36.661 ;
     RECT  0.192 36.613 0.456 36.949 ;
     RECT  0.192 36.949 1.272 37.091 ;
     RECT  0.192 37.091 1.176 37.573 ;
     RECT  20.208 36.563 24.312 37.573 ;
     RECT  26.4 35.363 27.012 37.667 ;
     RECT  0.144 37.573 1.176 38.053 ;
     RECT  0.144 38.053 1.32 38.195 ;
     RECT  20.208 37.573 24.504 38.195 ;
     RECT  34.32 36.563 38.616 38.197 ;
     RECT  34.32 38.197 38.76 38.339 ;
     RECT  0.144 38.195 1.224 38.435 ;
     RECT  20.256 38.195 24.504 38.531 ;
     RECT  15.9 36.661 18.912 38.675 ;
     RECT  32.1 33.731 32.412 38.725 ;
     RECT  18.432 38.675 18.912 39.493 ;
     RECT  0.144 38.435 0.264 39.635 ;
     RECT  0.24 39.635 0.264 39.731 ;
     RECT  15.9 38.675 17.352 39.779 ;
     RECT  34.32 38.339 38.616 39.877 ;
     RECT  18.432 39.493 19.272 40.405 ;
     RECT  20.256 38.531 24.312 40.405 ;
     RECT  15.9 39.779 16.824 40.595 ;
     RECT  29.4 36.515 29.712 40.981 ;
     RECT  34.32 39.877 38.76 41.075 ;
     RECT  0.288 39.781 0.312 41.221 ;
     RECT  18.432 40.405 24.312 41.267 ;
     RECT  0.288 41.221 0.36 41.269 ;
     RECT  0.24 41.269 0.36 41.365 ;
     RECT  18.432 41.267 19.272 41.651 ;
     RECT  34.56 41.075 38.76 41.653 ;
     RECT  34.56 41.653 38.808 41.699 ;
     RECT  31.68 38.725 32.412 41.891 ;
     RECT  0.144 41.365 0.36 41.941 ;
     RECT  0.144 41.941 1.176 42.179 ;
     RECT  25.536 40.837 25.56 42.227 ;
     RECT  34.608 41.699 38.808 42.275 ;
     RECT  0.144 42.179 0.264 42.419 ;
     RECT  2.304 36.613 14.568 42.469 ;
     RECT  20.256 41.267 24.312 42.565 ;
     RECT  18.432 41.651 18.912 42.709 ;
     RECT  15.9 40.595 16.728 43.285 ;
     RECT  17.952 42.709 18.912 43.285 ;
     RECT  2.304 42.469 14.808 43.379 ;
     RECT  20.016 42.565 24.312 43.379 ;
     RECT  0.24 42.419 0.264 43.859 ;
     RECT  29.28 40.981 29.712 43.861 ;
     RECT  2.4 43.379 14.808 44.099 ;
     RECT  34.608 42.275 38.76 44.483 ;
     RECT  28.752 43.861 29.712 44.485 ;
     RECT  28.752 44.485 30.408 44.627 ;
     RECT  15.9 43.285 18.912 44.725 ;
     RECT  20.064 43.379 24.312 44.725 ;
     RECT  32.1 41.891 32.412 45.157 ;
     RECT  29.28 44.627 30.408 45.827 ;
     RECT  34.656 44.483 38.76 46.019 ;
     RECT  29.28 45.827 29.712 46.259 ;
     RECT  26.7 37.667 27.012 46.741 ;
     RECT  2.4 44.099 14.568 46.787 ;
     RECT  32.1 45.157 33 46.787 ;
     RECT  34.8 46.019 38.76 46.787 ;
     RECT  26.7 46.741 27.144 46.883 ;
     RECT  15.9 44.725 24.312 47.171 ;
     RECT  15.9 47.171 17.448 47.891 ;
     RECT  15.9 47.891 17.064 48.083 ;
     RECT  32.1 46.787 32.412 48.421 ;
     RECT  15.9 48.083 16.728 48.755 ;
     RECT  3.984 46.787 14.568 48.757 ;
     RECT  15.9 48.755 16.392 48.757 ;
     RECT  3.984 48.757 16.392 49.043 ;
     RECT  37.5 46.787 38.76 49.475 ;
     RECT  2.4 46.787 2.856 49.523 ;
     RECT  4.032 49.043 16.392 49.619 ;
     RECT  34.8 46.787 36.456 49.619 ;
     RECT  37.5 49.475 38.712 49.667 ;
     RECT  37.5 49.667 38.664 49.811 ;
     RECT  32.1 48.421 32.856 49.957 ;
     RECT  25.68 46.213 25.704 50.003 ;
     RECT  18.432 47.171 24.312 50.149 ;
     RECT  18.432 50.149 24.504 50.195 ;
     RECT  4.032 49.619 16.344 50.627 ;
     RECT  5.1 50.627 16.344 50.677 ;
     RECT  32.1 49.957 33.096 50.771 ;
     RECT  36.096 49.619 36.456 50.771 ;
     RECT  18.432 50.195 19.944 51.155 ;
     RECT  21.168 50.195 24.504 51.347 ;
     RECT  5.1 50.677 16.632 51.395 ;
     RECT  26.7 46.883 27.012 51.445 ;
     RECT  21.168 51.347 24.408 51.779 ;
     RECT  36.24 50.771 36.456 51.875 ;
     RECT  32.1 50.771 32.616 51.925 ;
     RECT  31.968 51.925 32.616 51.971 ;
     RECT  26.7 51.445 27.912 52.739 ;
     RECT  21.168 51.779 24.312 52.837 ;
     RECT  20.976 52.837 24.312 52.979 ;
     RECT  18.432 51.155 19.704 52.981 ;
     RECT  5.1 51.395 12.072 53.075 ;
     RECT  4.032 50.627 4.056 53.363 ;
     RECT  36.432 51.875 36.456 53.363 ;
     RECT  21.072 52.979 24.312 53.557 ;
     RECT  31.968 51.971 32.412 53.797 ;
     RECT  13.2 51.395 16.632 53.893 ;
     RECT  5.1 53.075 11.256 53.939 ;
     RECT  26.7 52.739 27.288 53.939 ;
     RECT  12.24 53.893 16.632 54.083 ;
     RECT  6.672 53.939 11.256 54.373 ;
     RECT  12.24 54.083 16.212 54.373 ;
     RECT  34.8 49.619 35.112 54.661 ;
     RECT  18.096 52.981 19.704 54.709 ;
     RECT  5.1 53.939 5.592 54.755 ;
     RECT  21.072 53.557 25.272 54.851 ;
     RECT  6.672 54.373 16.212 55.379 ;
     RECT  21.12 54.851 25.272 55.379 ;
     RECT  34.8 54.661 35.352 55.427 ;
     RECT  31.968 53.797 32.712 55.571 ;
     RECT  17.76 54.709 19.704 55.811 ;
     RECT  21.12 55.379 22.92 55.955 ;
     RECT  21.12 55.955 21.864 56.003 ;
     RECT  21.12 56.003 21.612 56.051 ;
     RECT  17.76 55.811 19.176 56.389 ;
     RECT  34.8 55.427 35.112 56.485 ;
     RECT  6.672 55.379 14.52 56.677 ;
     RECT  15.9 55.379 16.212 56.677 ;
     RECT  32.1 55.571 32.712 56.869 ;
     RECT  6.672 56.677 16.212 56.915 ;
     RECT  31.968 56.869 32.712 56.915 ;
     RECT  24 55.379 25.272 56.917 ;
     RECT  2.4 49.523 2.712 56.965 ;
     RECT  17.616 56.389 19.176 56.965 ;
     RECT  7.488 56.915 16.212 57.155 ;
     RECT  21.168 56.051 21.612 57.253 ;
     RECT  34.56 56.485 35.112 57.349 ;
     RECT  17.616 56.965 19.368 57.443 ;
     RECT  28.368 56.389 28.392 57.443 ;
     RECT  18.096 57.443 19.176 57.635 ;
     RECT  22.896 55.955 22.92 57.635 ;
     RECT  21.12 57.253 21.612 57.685 ;
     RECT  24 56.917 25.416 57.731 ;
     RECT  5.1 54.755 5.412 57.973 ;
     RECT  12.24 57.155 16.212 58.069 ;
     RECT  7.488 57.155 10.812 58.117 ;
     RECT  7.488 58.117 11.208 58.163 ;
     RECT  12.24 58.069 16.824 58.163 ;
     RECT  9.456 58.163 11.208 58.501 ;
     RECT  12.24 58.163 14.52 58.501 ;
     RECT  4.992 57.973 5.412 58.549 ;
     RECT  2.4 56.965 3.624 58.645 ;
     RECT  9.456 58.501 14.52 58.691 ;
     RECT  21.072 57.685 21.612 58.693 ;
     RECT  11.952 58.691 14.52 58.787 ;
     RECT  15.504 58.163 16.824 59.219 ;
     RECT  21.024 58.693 21.612 59.267 ;
     RECT  2.304 58.645 3.624 59.315 ;
     RECT  18.096 57.635 19.08 59.315 ;
     RECT  15.9 59.219 16.824 59.363 ;
     RECT  13.056 58.787 14.52 59.603 ;
     RECT  24 57.731 25.272 59.605 ;
     RECT  24 59.605 25.368 59.651 ;
     RECT  25.344 59.651 25.368 59.749 ;
     RECT  4.992 58.549 5.64 59.797 ;
     RECT  7.488 58.163 8.424 59.797 ;
     RECT  2.304 59.315 2.712 59.891 ;
     RECT  18.096 59.315 18.912 59.941 ;
     RECT  31.968 56.915 32.412 60.133 ;
     RECT  24 59.651 24.312 60.277 ;
     RECT  25.344 59.749 25.56 60.323 ;
     RECT  2.4 59.891 2.712 60.373 ;
     RECT  34.272 57.349 35.112 60.419 ;
     RECT  11.952 58.787 11.976 60.467 ;
     RECT  7.44 59.797 8.424 60.515 ;
     RECT  34.512 60.419 35.112 60.613 ;
     RECT  13.056 59.603 13.608 60.805 ;
     RECT  7.44 60.515 8.328 60.995 ;
     RECT  18 59.941 18.912 61.139 ;
     RECT  2.4 60.373 3.576 61.331 ;
     RECT  23.808 60.277 24.312 61.429 ;
     RECT  13.056 60.805 13.656 61.619 ;
     RECT  21.168 59.267 21.612 61.621 ;
     RECT  13.056 61.619 13.608 61.715 ;
     RECT  9.456 58.691 10.812 61.765 ;
     RECT  34.512 60.613 35.208 61.907 ;
     RECT  15.9 59.363 16.212 62.005 ;
     RECT  4.992 59.797 6.312 62.195 ;
     RECT  15.792 62.005 16.212 62.437 ;
     RECT  7.44 60.995 8.232 62.533 ;
     RECT  6.624 62.533 8.232 62.579 ;
     RECT  23.568 61.429 24.312 62.677 ;
     RECT  13.056 61.715 13.512 62.771 ;
     RECT  22.752 62.677 24.312 62.771 ;
     RECT  21.12 61.621 21.612 62.773 ;
     RECT  22.752 62.771 22.776 62.773 ;
     RECT  21.12 62.773 22.776 62.819 ;
     RECT  7.632 62.579 8.232 62.867 ;
     RECT  15.072 62.437 16.212 63.251 ;
     RECT  34.656 61.907 35.208 63.493 ;
     RECT  34.656 63.493 35.256 63.539 ;
     RECT  9.456 61.765 11.736 64.067 ;
     RECT  21.12 62.819 22.392 64.163 ;
     RECT  4.992 62.195 5.64 64.165 ;
     RECT  7.632 62.867 8.112 64.451 ;
     RECT  31.92 60.133 32.412 64.451 ;
     RECT  21.168 64.163 22.392 64.595 ;
     RECT  2.4 61.331 2.712 64.933 ;
     RECT  7.8 64.451 8.112 64.933 ;
     RECT  4.272 64.165 5.64 65.027 ;
     RECT  9.456 64.067 10.812 65.171 ;
     RECT  29.4 46.259 29.712 65.221 ;
     RECT  31.968 64.451 32.412 65.507 ;
     RECT  10.368 65.171 10.812 65.603 ;
     RECT  2.304 64.933 2.712 66.565 ;
     RECT  32.1 65.507 32.412 66.565 ;
     RECT  22.752 65.845 22.776 66.755 ;
     RECT  28.704 65.221 29.712 66.755 ;
     RECT  2.304 66.565 3.096 66.803 ;
     RECT  2.4 66.803 3.096 67.813 ;
     RECT  21.168 64.595 21.612 67.859 ;
     RECT  4.992 65.027 5.64 68.341 ;
     RECT  6.624 62.579 6.648 68.341 ;
     RECT  4.992 68.341 6.648 68.435 ;
     RECT  34.8 63.539 35.256 68.483 ;
     RECT  4.992 68.435 6.504 68.531 ;
     RECT  7.8 64.933 8.232 68.627 ;
     RECT  2.4 67.813 3.384 68.675 ;
     RECT  5.1 68.531 6.504 68.675 ;
     RECT  25.344 60.323 25.368 68.963 ;
     RECT  31.968 66.565 32.412 69.397 ;
     RECT  2.4 68.675 2.856 69.683 ;
     RECT  3.888 69.349 3.912 70.691 ;
     RECT  34.8 68.483 35.208 70.739 ;
     RECT  6.48 68.675 6.504 71.075 ;
     RECT  29.4 66.755 29.712 72.421 ;
     RECT  29.136 72.421 29.712 72.995 ;
     RECT  31.296 69.397 32.412 74.339 ;
     RECT  2.4 69.683 2.712 75.609 ;
     RECT  5.1 68.675 5.412 75.609 ;
     RECT  7.8 68.627 8.112 75.609 ;
     RECT  10.5 65.603 10.812 75.609 ;
     RECT  13.2 62.771 13.512 75.609 ;
     RECT  15.9 63.251 16.212 75.609 ;
     RECT  18.6 61.139 18.912 75.609 ;
     RECT  21.3 67.859 21.612 75.609 ;
     RECT  24 62.771 24.312 75.609 ;
     RECT  26.7 53.939 27.012 75.609 ;
     RECT  29.4 72.995 29.712 75.609 ;
     RECT  32.1 74.339 32.412 75.609 ;
     RECT  34.8 70.739 35.112 75.609 ;
     RECT  37.5 49.811 37.812 75.609 ;
     RECT  40.2 2.151 40.512 75.609 ;
     RECT  2.4 75.609 2.52 75.623 ;
     RECT  5.1 75.609 5.22 75.623 ;
     RECT  7.8 75.609 7.92 75.623 ;
     RECT  10.5 75.609 10.62 75.623 ;
     RECT  13.2 75.609 13.32 75.623 ;
     RECT  15.9 75.609 16.02 75.623 ;
     RECT  18.6 75.609 18.72 75.623 ;
     RECT  21.3 75.609 21.42 75.623 ;
     RECT  24 75.609 24.12 75.623 ;
     RECT  26.7 75.609 26.82 75.623 ;
     RECT  29.4 75.609 29.52 75.623 ;
     RECT  32.1 75.609 32.22 75.623 ;
     RECT  34.8 75.609 34.92 75.623 ;
     RECT  37.5 75.609 37.62 75.623 ;
     RECT  40.2 75.609 40.32 75.623 ;
  END
END dsfd_node_LLd
END LIBRARY
